# Generated by FakeRAM 2.0
VERSION 5.7 ;
BUSBITCHARS "[]" ;
PROPERTYDEFINITIONS
  MACRO width INTEGER ;
  MACRO depth INTEGER ;
  MACRO banks INTEGER ;
END PROPERTYDEFINITIONS
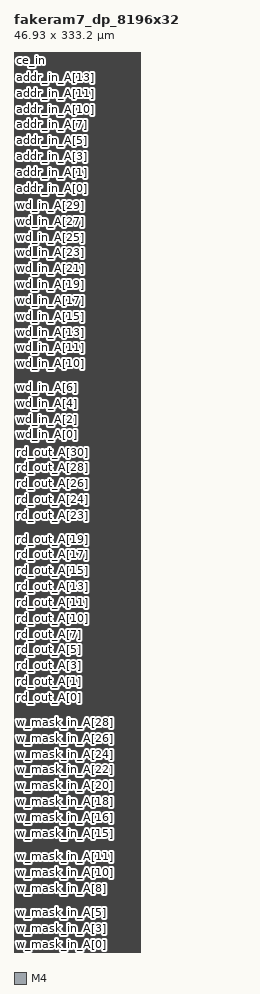
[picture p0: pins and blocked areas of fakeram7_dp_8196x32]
MACRO fakeram7_dp_8196x32
  PROPERTY width 32 ;
  PROPERTY depth 8196 ;
  PROPERTY banks 8 ;
  FOREIGN fakeram7_dp_8196x32 0 0 ;
  SYMMETRY X Y ;
  SIZE 46.930 BY 333.200 ;
  CLASS BLOCK ;
  PIN w_mask_in_A[0]
    DIRECTION INPUT ;
    USE SIGNAL ;
    SHAPE ABUTMENT ;
    PORT
      LAYER M4 ;
      RECT 0.000 0.048 0.024 0.072 ;
    END
  END w_mask_in_A[0]
  PIN w_mask_in_B[0]
    DIRECTION INPUT ;
    USE SIGNAL ;
    SHAPE ABUTMENT ;
    PORT
      LAYER M4 ;
      RECT 46.906 0.048 46.930 0.072 ;
    END
  END w_mask_in_B[0]
  PIN w_mask_in_A[1]
    DIRECTION INPUT ;
    USE SIGNAL ;
    SHAPE ABUTMENT ;
    PORT
      LAYER M4 ;
      RECT 0.000 2.976 0.024 3.000 ;
    END
  END w_mask_in_A[1]
  PIN w_mask_in_B[1]
    DIRECTION INPUT ;
    USE SIGNAL ;
    SHAPE ABUTMENT ;
    PORT
      LAYER M4 ;
      RECT 46.906 2.976 46.930 3.000 ;
    END
  END w_mask_in_B[1]
  PIN w_mask_in_A[2]
    DIRECTION INPUT ;
    USE SIGNAL ;
    SHAPE ABUTMENT ;
    PORT
      LAYER M4 ;
      RECT 0.000 5.904 0.024 5.928 ;
    END
  END w_mask_in_A[2]
  PIN w_mask_in_B[2]
    DIRECTION INPUT ;
    USE SIGNAL ;
    SHAPE ABUTMENT ;
    PORT
      LAYER M4 ;
      RECT 46.906 5.904 46.930 5.928 ;
    END
  END w_mask_in_B[2]
  PIN w_mask_in_A[3]
    DIRECTION INPUT ;
    USE SIGNAL ;
    SHAPE ABUTMENT ;
    PORT
      LAYER M4 ;
      RECT 0.000 8.832 0.024 8.856 ;
    END
  END w_mask_in_A[3]
  PIN w_mask_in_B[3]
    DIRECTION INPUT ;
    USE SIGNAL ;
    SHAPE ABUTMENT ;
    PORT
      LAYER M4 ;
      RECT 46.906 8.832 46.930 8.856 ;
    END
  END w_mask_in_B[3]
  PIN w_mask_in_A[4]
    DIRECTION INPUT ;
    USE SIGNAL ;
    SHAPE ABUTMENT ;
    PORT
      LAYER M4 ;
      RECT 0.000 11.760 0.024 11.784 ;
    END
  END w_mask_in_A[4]
  PIN w_mask_in_B[4]
    DIRECTION INPUT ;
    USE SIGNAL ;
    SHAPE ABUTMENT ;
    PORT
      LAYER M4 ;
      RECT 46.906 11.760 46.930 11.784 ;
    END
  END w_mask_in_B[4]
  PIN w_mask_in_A[5]
    DIRECTION INPUT ;
    USE SIGNAL ;
    SHAPE ABUTMENT ;
    PORT
      LAYER M4 ;
      RECT 0.000 14.688 0.024 14.712 ;
    END
  END w_mask_in_A[5]
  PIN w_mask_in_B[5]
    DIRECTION INPUT ;
    USE SIGNAL ;
    SHAPE ABUTMENT ;
    PORT
      LAYER M4 ;
      RECT 46.906 14.688 46.930 14.712 ;
    END
  END w_mask_in_B[5]
  PIN w_mask_in_A[6]
    DIRECTION INPUT ;
    USE SIGNAL ;
    SHAPE ABUTMENT ;
    PORT
      LAYER M4 ;
      RECT 0.000 17.616 0.024 17.640 ;
    END
  END w_mask_in_A[6]
  PIN w_mask_in_B[6]
    DIRECTION INPUT ;
    USE SIGNAL ;
    SHAPE ABUTMENT ;
    PORT
      LAYER M4 ;
      RECT 46.906 17.616 46.930 17.640 ;
    END
  END w_mask_in_B[6]
  PIN w_mask_in_A[7]
    DIRECTION INPUT ;
    USE SIGNAL ;
    SHAPE ABUTMENT ;
    PORT
      LAYER M4 ;
      RECT 0.000 20.544 0.024 20.568 ;
    END
  END w_mask_in_A[7]
  PIN w_mask_in_B[7]
    DIRECTION INPUT ;
    USE SIGNAL ;
    SHAPE ABUTMENT ;
    PORT
      LAYER M4 ;
      RECT 46.906 20.544 46.930 20.568 ;
    END
  END w_mask_in_B[7]
  PIN w_mask_in_A[8]
    DIRECTION INPUT ;
    USE SIGNAL ;
    SHAPE ABUTMENT ;
    PORT
      LAYER M4 ;
      RECT 0.000 23.472 0.024 23.496 ;
    END
  END w_mask_in_A[8]
  PIN w_mask_in_B[8]
    DIRECTION INPUT ;
    USE SIGNAL ;
    SHAPE ABUTMENT ;
    PORT
      LAYER M4 ;
      RECT 46.906 23.472 46.930 23.496 ;
    END
  END w_mask_in_B[8]
  PIN w_mask_in_A[9]
    DIRECTION INPUT ;
    USE SIGNAL ;
    SHAPE ABUTMENT ;
    PORT
      LAYER M4 ;
      RECT 0.000 26.400 0.024 26.424 ;
    END
  END w_mask_in_A[9]
  PIN w_mask_in_B[9]
    DIRECTION INPUT ;
    USE SIGNAL ;
    SHAPE ABUTMENT ;
    PORT
      LAYER M4 ;
      RECT 46.906 26.400 46.930 26.424 ;
    END
  END w_mask_in_B[9]
  PIN w_mask_in_A[10]
    DIRECTION INPUT ;
    USE SIGNAL ;
    SHAPE ABUTMENT ;
    PORT
      LAYER M4 ;
      RECT 0.000 29.328 0.024 29.352 ;
    END
  END w_mask_in_A[10]
  PIN w_mask_in_B[10]
    DIRECTION INPUT ;
    USE SIGNAL ;
    SHAPE ABUTMENT ;
    PORT
      LAYER M4 ;
      RECT 46.906 29.328 46.930 29.352 ;
    END
  END w_mask_in_B[10]
  PIN w_mask_in_A[11]
    DIRECTION INPUT ;
    USE SIGNAL ;
    SHAPE ABUTMENT ;
    PORT
      LAYER M4 ;
      RECT 0.000 32.256 0.024 32.280 ;
    END
  END w_mask_in_A[11]
  PIN w_mask_in_B[11]
    DIRECTION INPUT ;
    USE SIGNAL ;
    SHAPE ABUTMENT ;
    PORT
      LAYER M4 ;
      RECT 46.906 32.256 46.930 32.280 ;
    END
  END w_mask_in_B[11]
  PIN w_mask_in_A[12]
    DIRECTION INPUT ;
    USE SIGNAL ;
    SHAPE ABUTMENT ;
    PORT
      LAYER M4 ;
      RECT 0.000 35.184 0.024 35.208 ;
    END
  END w_mask_in_A[12]
  PIN w_mask_in_B[12]
    DIRECTION INPUT ;
    USE SIGNAL ;
    SHAPE ABUTMENT ;
    PORT
      LAYER M4 ;
      RECT 46.906 35.184 46.930 35.208 ;
    END
  END w_mask_in_B[12]
  PIN w_mask_in_A[13]
    DIRECTION INPUT ;
    USE SIGNAL ;
    SHAPE ABUTMENT ;
    PORT
      LAYER M4 ;
      RECT 0.000 38.112 0.024 38.136 ;
    END
  END w_mask_in_A[13]
  PIN w_mask_in_B[13]
    DIRECTION INPUT ;
    USE SIGNAL ;
    SHAPE ABUTMENT ;
    PORT
      LAYER M4 ;
      RECT 46.906 38.112 46.930 38.136 ;
    END
  END w_mask_in_B[13]
  PIN w_mask_in_A[14]
    DIRECTION INPUT ;
    USE SIGNAL ;
    SHAPE ABUTMENT ;
    PORT
      LAYER M4 ;
      RECT 0.000 41.040 0.024 41.064 ;
    END
  END w_mask_in_A[14]
  PIN w_mask_in_B[14]
    DIRECTION INPUT ;
    USE SIGNAL ;
    SHAPE ABUTMENT ;
    PORT
      LAYER M4 ;
      RECT 46.906 41.040 46.930 41.064 ;
    END
  END w_mask_in_B[14]
  PIN w_mask_in_A[15]
    DIRECTION INPUT ;
    USE SIGNAL ;
    SHAPE ABUTMENT ;
    PORT
      LAYER M4 ;
      RECT 0.000 43.968 0.024 43.992 ;
    END
  END w_mask_in_A[15]
  PIN w_mask_in_B[15]
    DIRECTION INPUT ;
    USE SIGNAL ;
    SHAPE ABUTMENT ;
    PORT
      LAYER M4 ;
      RECT 46.906 43.968 46.930 43.992 ;
    END
  END w_mask_in_B[15]
  PIN w_mask_in_A[16]
    DIRECTION INPUT ;
    USE SIGNAL ;
    SHAPE ABUTMENT ;
    PORT
      LAYER M4 ;
      RECT 0.000 46.896 0.024 46.920 ;
    END
  END w_mask_in_A[16]
  PIN w_mask_in_B[16]
    DIRECTION INPUT ;
    USE SIGNAL ;
    SHAPE ABUTMENT ;
    PORT
      LAYER M4 ;
      RECT 46.906 46.896 46.930 46.920 ;
    END
  END w_mask_in_B[16]
  PIN w_mask_in_A[17]
    DIRECTION INPUT ;
    USE SIGNAL ;
    SHAPE ABUTMENT ;
    PORT
      LAYER M4 ;
      RECT 0.000 49.824 0.024 49.848 ;
    END
  END w_mask_in_A[17]
  PIN w_mask_in_B[17]
    DIRECTION INPUT ;
    USE SIGNAL ;
    SHAPE ABUTMENT ;
    PORT
      LAYER M4 ;
      RECT 46.906 49.824 46.930 49.848 ;
    END
  END w_mask_in_B[17]
  PIN w_mask_in_A[18]
    DIRECTION INPUT ;
    USE SIGNAL ;
    SHAPE ABUTMENT ;
    PORT
      LAYER M4 ;
      RECT 0.000 52.752 0.024 52.776 ;
    END
  END w_mask_in_A[18]
  PIN w_mask_in_B[18]
    DIRECTION INPUT ;
    USE SIGNAL ;
    SHAPE ABUTMENT ;
    PORT
      LAYER M4 ;
      RECT 46.906 52.752 46.930 52.776 ;
    END
  END w_mask_in_B[18]
  PIN w_mask_in_A[19]
    DIRECTION INPUT ;
    USE SIGNAL ;
    SHAPE ABUTMENT ;
    PORT
      LAYER M4 ;
      RECT 0.000 55.680 0.024 55.704 ;
    END
  END w_mask_in_A[19]
  PIN w_mask_in_B[19]
    DIRECTION INPUT ;
    USE SIGNAL ;
    SHAPE ABUTMENT ;
    PORT
      LAYER M4 ;
      RECT 46.906 55.680 46.930 55.704 ;
    END
  END w_mask_in_B[19]
  PIN w_mask_in_A[20]
    DIRECTION INPUT ;
    USE SIGNAL ;
    SHAPE ABUTMENT ;
    PORT
      LAYER M4 ;
      RECT 0.000 58.608 0.024 58.632 ;
    END
  END w_mask_in_A[20]
  PIN w_mask_in_B[20]
    DIRECTION INPUT ;
    USE SIGNAL ;
    SHAPE ABUTMENT ;
    PORT
      LAYER M4 ;
      RECT 46.906 58.608 46.930 58.632 ;
    END
  END w_mask_in_B[20]
  PIN w_mask_in_A[21]
    DIRECTION INPUT ;
    USE SIGNAL ;
    SHAPE ABUTMENT ;
    PORT
      LAYER M4 ;
      RECT 0.000 61.536 0.024 61.560 ;
    END
  END w_mask_in_A[21]
  PIN w_mask_in_B[21]
    DIRECTION INPUT ;
    USE SIGNAL ;
    SHAPE ABUTMENT ;
    PORT
      LAYER M4 ;
      RECT 46.906 61.536 46.930 61.560 ;
    END
  END w_mask_in_B[21]
  PIN w_mask_in_A[22]
    DIRECTION INPUT ;
    USE SIGNAL ;
    SHAPE ABUTMENT ;
    PORT
      LAYER M4 ;
      RECT 0.000 64.464 0.024 64.488 ;
    END
  END w_mask_in_A[22]
  PIN w_mask_in_B[22]
    DIRECTION INPUT ;
    USE SIGNAL ;
    SHAPE ABUTMENT ;
    PORT
      LAYER M4 ;
      RECT 46.906 64.464 46.930 64.488 ;
    END
  END w_mask_in_B[22]
  PIN w_mask_in_A[23]
    DIRECTION INPUT ;
    USE SIGNAL ;
    SHAPE ABUTMENT ;
    PORT
      LAYER M4 ;
      RECT 0.000 67.392 0.024 67.416 ;
    END
  END w_mask_in_A[23]
  PIN w_mask_in_B[23]
    DIRECTION INPUT ;
    USE SIGNAL ;
    SHAPE ABUTMENT ;
    PORT
      LAYER M4 ;
      RECT 46.906 67.392 46.930 67.416 ;
    END
  END w_mask_in_B[23]
  PIN w_mask_in_A[24]
    DIRECTION INPUT ;
    USE SIGNAL ;
    SHAPE ABUTMENT ;
    PORT
      LAYER M4 ;
      RECT 0.000 70.320 0.024 70.344 ;
    END
  END w_mask_in_A[24]
  PIN w_mask_in_B[24]
    DIRECTION INPUT ;
    USE SIGNAL ;
    SHAPE ABUTMENT ;
    PORT
      LAYER M4 ;
      RECT 46.906 70.320 46.930 70.344 ;
    END
  END w_mask_in_B[24]
  PIN w_mask_in_A[25]
    DIRECTION INPUT ;
    USE SIGNAL ;
    SHAPE ABUTMENT ;
    PORT
      LAYER M4 ;
      RECT 0.000 73.248 0.024 73.272 ;
    END
  END w_mask_in_A[25]
  PIN w_mask_in_B[25]
    DIRECTION INPUT ;
    USE SIGNAL ;
    SHAPE ABUTMENT ;
    PORT
      LAYER M4 ;
      RECT 46.906 73.248 46.930 73.272 ;
    END
  END w_mask_in_B[25]
  PIN w_mask_in_A[26]
    DIRECTION INPUT ;
    USE SIGNAL ;
    SHAPE ABUTMENT ;
    PORT
      LAYER M4 ;
      RECT 0.000 76.176 0.024 76.200 ;
    END
  END w_mask_in_A[26]
  PIN w_mask_in_B[26]
    DIRECTION INPUT ;
    USE SIGNAL ;
    SHAPE ABUTMENT ;
    PORT
      LAYER M4 ;
      RECT 46.906 76.176 46.930 76.200 ;
    END
  END w_mask_in_B[26]
  PIN w_mask_in_A[27]
    DIRECTION INPUT ;
    USE SIGNAL ;
    SHAPE ABUTMENT ;
    PORT
      LAYER M4 ;
      RECT 0.000 79.104 0.024 79.128 ;
    END
  END w_mask_in_A[27]
  PIN w_mask_in_B[27]
    DIRECTION INPUT ;
    USE SIGNAL ;
    SHAPE ABUTMENT ;
    PORT
      LAYER M4 ;
      RECT 46.906 79.104 46.930 79.128 ;
    END
  END w_mask_in_B[27]
  PIN w_mask_in_A[28]
    DIRECTION INPUT ;
    USE SIGNAL ;
    SHAPE ABUTMENT ;
    PORT
      LAYER M4 ;
      RECT 0.000 82.032 0.024 82.056 ;
    END
  END w_mask_in_A[28]
  PIN w_mask_in_B[28]
    DIRECTION INPUT ;
    USE SIGNAL ;
    SHAPE ABUTMENT ;
    PORT
      LAYER M4 ;
      RECT 46.906 82.032 46.930 82.056 ;
    END
  END w_mask_in_B[28]
  PIN w_mask_in_A[29]
    DIRECTION INPUT ;
    USE SIGNAL ;
    SHAPE ABUTMENT ;
    PORT
      LAYER M4 ;
      RECT 0.000 84.960 0.024 84.984 ;
    END
  END w_mask_in_A[29]
  PIN w_mask_in_B[29]
    DIRECTION INPUT ;
    USE SIGNAL ;
    SHAPE ABUTMENT ;
    PORT
      LAYER M4 ;
      RECT 46.906 84.960 46.930 84.984 ;
    END
  END w_mask_in_B[29]
  PIN w_mask_in_A[30]
    DIRECTION INPUT ;
    USE SIGNAL ;
    SHAPE ABUTMENT ;
    PORT
      LAYER M4 ;
      RECT 0.000 87.888 0.024 87.912 ;
    END
  END w_mask_in_A[30]
  PIN w_mask_in_B[30]
    DIRECTION INPUT ;
    USE SIGNAL ;
    SHAPE ABUTMENT ;
    PORT
      LAYER M4 ;
      RECT 46.906 87.888 46.930 87.912 ;
    END
  END w_mask_in_B[30]
  PIN w_mask_in_A[31]
    DIRECTION INPUT ;
    USE SIGNAL ;
    SHAPE ABUTMENT ;
    PORT
      LAYER M4 ;
      RECT 0.000 90.816 0.024 90.840 ;
    END
  END w_mask_in_A[31]
  PIN w_mask_in_B[31]
    DIRECTION INPUT ;
    USE SIGNAL ;
    SHAPE ABUTMENT ;
    PORT
      LAYER M4 ;
      RECT 46.906 90.816 46.930 90.840 ;
    END
  END w_mask_in_B[31]
  PIN rd_out_A[0]
    DIRECTION OUTPUT ;
    USE SIGNAL ;
    SHAPE ABUTMENT ;
    PORT
      LAYER M4 ;
      RECT 0.000 94.272 0.024 94.296 ;
    END
  END rd_out_A[0]
  PIN rd_out_B[0]
    DIRECTION OUTPUT ;
    USE SIGNAL ;
    SHAPE ABUTMENT ;
    PORT
      LAYER M4 ;
      RECT 46.906 94.272 46.930 94.296 ;
    END
  END rd_out_B[0]
  PIN rd_out_A[1]
    DIRECTION OUTPUT ;
    USE SIGNAL ;
    SHAPE ABUTMENT ;
    PORT
      LAYER M4 ;
      RECT 0.000 97.200 0.024 97.224 ;
    END
  END rd_out_A[1]
  PIN rd_out_B[1]
    DIRECTION OUTPUT ;
    USE SIGNAL ;
    SHAPE ABUTMENT ;
    PORT
      LAYER M4 ;
      RECT 46.906 97.200 46.930 97.224 ;
    END
  END rd_out_B[1]
  PIN rd_out_A[2]
    DIRECTION OUTPUT ;
    USE SIGNAL ;
    SHAPE ABUTMENT ;
    PORT
      LAYER M4 ;
      RECT 0.000 100.128 0.024 100.152 ;
    END
  END rd_out_A[2]
  PIN rd_out_B[2]
    DIRECTION OUTPUT ;
    USE SIGNAL ;
    SHAPE ABUTMENT ;
    PORT
      LAYER M4 ;
      RECT 46.906 100.128 46.930 100.152 ;
    END
  END rd_out_B[2]
  PIN rd_out_A[3]
    DIRECTION OUTPUT ;
    USE SIGNAL ;
    SHAPE ABUTMENT ;
    PORT
      LAYER M4 ;
      RECT 0.000 103.056 0.024 103.080 ;
    END
  END rd_out_A[3]
  PIN rd_out_B[3]
    DIRECTION OUTPUT ;
    USE SIGNAL ;
    SHAPE ABUTMENT ;
    PORT
      LAYER M4 ;
      RECT 46.906 103.056 46.930 103.080 ;
    END
  END rd_out_B[3]
  PIN rd_out_A[4]
    DIRECTION OUTPUT ;
    USE SIGNAL ;
    SHAPE ABUTMENT ;
    PORT
      LAYER M4 ;
      RECT 0.000 105.984 0.024 106.008 ;
    END
  END rd_out_A[4]
  PIN rd_out_B[4]
    DIRECTION OUTPUT ;
    USE SIGNAL ;
    SHAPE ABUTMENT ;
    PORT
      LAYER M4 ;
      RECT 46.906 105.984 46.930 106.008 ;
    END
  END rd_out_B[4]
  PIN rd_out_A[5]
    DIRECTION OUTPUT ;
    USE SIGNAL ;
    SHAPE ABUTMENT ;
    PORT
      LAYER M4 ;
      RECT 0.000 108.912 0.024 108.936 ;
    END
  END rd_out_A[5]
  PIN rd_out_B[5]
    DIRECTION OUTPUT ;
    USE SIGNAL ;
    SHAPE ABUTMENT ;
    PORT
      LAYER M4 ;
      RECT 46.906 108.912 46.930 108.936 ;
    END
  END rd_out_B[5]
  PIN rd_out_A[6]
    DIRECTION OUTPUT ;
    USE SIGNAL ;
    SHAPE ABUTMENT ;
    PORT
      LAYER M4 ;
      RECT 0.000 111.840 0.024 111.864 ;
    END
  END rd_out_A[6]
  PIN rd_out_B[6]
    DIRECTION OUTPUT ;
    USE SIGNAL ;
    SHAPE ABUTMENT ;
    PORT
      LAYER M4 ;
      RECT 46.906 111.840 46.930 111.864 ;
    END
  END rd_out_B[6]
  PIN rd_out_A[7]
    DIRECTION OUTPUT ;
    USE SIGNAL ;
    SHAPE ABUTMENT ;
    PORT
      LAYER M4 ;
      RECT 0.000 114.768 0.024 114.792 ;
    END
  END rd_out_A[7]
  PIN rd_out_B[7]
    DIRECTION OUTPUT ;
    USE SIGNAL ;
    SHAPE ABUTMENT ;
    PORT
      LAYER M4 ;
      RECT 46.906 114.768 46.930 114.792 ;
    END
  END rd_out_B[7]
  PIN rd_out_A[8]
    DIRECTION OUTPUT ;
    USE SIGNAL ;
    SHAPE ABUTMENT ;
    PORT
      LAYER M4 ;
      RECT 0.000 117.696 0.024 117.720 ;
    END
  END rd_out_A[8]
  PIN rd_out_B[8]
    DIRECTION OUTPUT ;
    USE SIGNAL ;
    SHAPE ABUTMENT ;
    PORT
      LAYER M4 ;
      RECT 46.906 117.696 46.930 117.720 ;
    END
  END rd_out_B[8]
  PIN rd_out_A[9]
    DIRECTION OUTPUT ;
    USE SIGNAL ;
    SHAPE ABUTMENT ;
    PORT
      LAYER M4 ;
      RECT 0.000 120.624 0.024 120.648 ;
    END
  END rd_out_A[9]
  PIN rd_out_B[9]
    DIRECTION OUTPUT ;
    USE SIGNAL ;
    SHAPE ABUTMENT ;
    PORT
      LAYER M4 ;
      RECT 46.906 120.624 46.930 120.648 ;
    END
  END rd_out_B[9]
  PIN rd_out_A[10]
    DIRECTION OUTPUT ;
    USE SIGNAL ;
    SHAPE ABUTMENT ;
    PORT
      LAYER M4 ;
      RECT 0.000 123.552 0.024 123.576 ;
    END
  END rd_out_A[10]
  PIN rd_out_B[10]
    DIRECTION OUTPUT ;
    USE SIGNAL ;
    SHAPE ABUTMENT ;
    PORT
      LAYER M4 ;
      RECT 46.906 123.552 46.930 123.576 ;
    END
  END rd_out_B[10]
  PIN rd_out_A[11]
    DIRECTION OUTPUT ;
    USE SIGNAL ;
    SHAPE ABUTMENT ;
    PORT
      LAYER M4 ;
      RECT 0.000 126.480 0.024 126.504 ;
    END
  END rd_out_A[11]
  PIN rd_out_B[11]
    DIRECTION OUTPUT ;
    USE SIGNAL ;
    SHAPE ABUTMENT ;
    PORT
      LAYER M4 ;
      RECT 46.906 126.480 46.930 126.504 ;
    END
  END rd_out_B[11]
  PIN rd_out_A[12]
    DIRECTION OUTPUT ;
    USE SIGNAL ;
    SHAPE ABUTMENT ;
    PORT
      LAYER M4 ;
      RECT 0.000 129.408 0.024 129.432 ;
    END
  END rd_out_A[12]
  PIN rd_out_B[12]
    DIRECTION OUTPUT ;
    USE SIGNAL ;
    SHAPE ABUTMENT ;
    PORT
      LAYER M4 ;
      RECT 46.906 129.408 46.930 129.432 ;
    END
  END rd_out_B[12]
  PIN rd_out_A[13]
    DIRECTION OUTPUT ;
    USE SIGNAL ;
    SHAPE ABUTMENT ;
    PORT
      LAYER M4 ;
      RECT 0.000 132.336 0.024 132.360 ;
    END
  END rd_out_A[13]
  PIN rd_out_B[13]
    DIRECTION OUTPUT ;
    USE SIGNAL ;
    SHAPE ABUTMENT ;
    PORT
      LAYER M4 ;
      RECT 46.906 132.336 46.930 132.360 ;
    END
  END rd_out_B[13]
  PIN rd_out_A[14]
    DIRECTION OUTPUT ;
    USE SIGNAL ;
    SHAPE ABUTMENT ;
    PORT
      LAYER M4 ;
      RECT 0.000 135.264 0.024 135.288 ;
    END
  END rd_out_A[14]
  PIN rd_out_B[14]
    DIRECTION OUTPUT ;
    USE SIGNAL ;
    SHAPE ABUTMENT ;
    PORT
      LAYER M4 ;
      RECT 46.906 135.264 46.930 135.288 ;
    END
  END rd_out_B[14]
  PIN rd_out_A[15]
    DIRECTION OUTPUT ;
    USE SIGNAL ;
    SHAPE ABUTMENT ;
    PORT
      LAYER M4 ;
      RECT 0.000 138.192 0.024 138.216 ;
    END
  END rd_out_A[15]
  PIN rd_out_B[15]
    DIRECTION OUTPUT ;
    USE SIGNAL ;
    SHAPE ABUTMENT ;
    PORT
      LAYER M4 ;
      RECT 46.906 138.192 46.930 138.216 ;
    END
  END rd_out_B[15]
  PIN rd_out_A[16]
    DIRECTION OUTPUT ;
    USE SIGNAL ;
    SHAPE ABUTMENT ;
    PORT
      LAYER M4 ;
      RECT 0.000 141.120 0.024 141.144 ;
    END
  END rd_out_A[16]
  PIN rd_out_B[16]
    DIRECTION OUTPUT ;
    USE SIGNAL ;
    SHAPE ABUTMENT ;
    PORT
      LAYER M4 ;
      RECT 46.906 141.120 46.930 141.144 ;
    END
  END rd_out_B[16]
  PIN rd_out_A[17]
    DIRECTION OUTPUT ;
    USE SIGNAL ;
    SHAPE ABUTMENT ;
    PORT
      LAYER M4 ;
      RECT 0.000 144.048 0.024 144.072 ;
    END
  END rd_out_A[17]
  PIN rd_out_B[17]
    DIRECTION OUTPUT ;
    USE SIGNAL ;
    SHAPE ABUTMENT ;
    PORT
      LAYER M4 ;
      RECT 46.906 144.048 46.930 144.072 ;
    END
  END rd_out_B[17]
  PIN rd_out_A[18]
    DIRECTION OUTPUT ;
    USE SIGNAL ;
    SHAPE ABUTMENT ;
    PORT
      LAYER M4 ;
      RECT 0.000 146.976 0.024 147.000 ;
    END
  END rd_out_A[18]
  PIN rd_out_B[18]
    DIRECTION OUTPUT ;
    USE SIGNAL ;
    SHAPE ABUTMENT ;
    PORT
      LAYER M4 ;
      RECT 46.906 146.976 46.930 147.000 ;
    END
  END rd_out_B[18]
  PIN rd_out_A[19]
    DIRECTION OUTPUT ;
    USE SIGNAL ;
    SHAPE ABUTMENT ;
    PORT
      LAYER M4 ;
      RECT 0.000 149.904 0.024 149.928 ;
    END
  END rd_out_A[19]
  PIN rd_out_B[19]
    DIRECTION OUTPUT ;
    USE SIGNAL ;
    SHAPE ABUTMENT ;
    PORT
      LAYER M4 ;
      RECT 46.906 149.904 46.930 149.928 ;
    END
  END rd_out_B[19]
  PIN rd_out_A[20]
    DIRECTION OUTPUT ;
    USE SIGNAL ;
    SHAPE ABUTMENT ;
    PORT
      LAYER M4 ;
      RECT 0.000 152.832 0.024 152.856 ;
    END
  END rd_out_A[20]
  PIN rd_out_B[20]
    DIRECTION OUTPUT ;
    USE SIGNAL ;
    SHAPE ABUTMENT ;
    PORT
      LAYER M4 ;
      RECT 46.906 152.832 46.930 152.856 ;
    END
  END rd_out_B[20]
  PIN rd_out_A[21]
    DIRECTION OUTPUT ;
    USE SIGNAL ;
    SHAPE ABUTMENT ;
    PORT
      LAYER M4 ;
      RECT 0.000 155.760 0.024 155.784 ;
    END
  END rd_out_A[21]
  PIN rd_out_B[21]
    DIRECTION OUTPUT ;
    USE SIGNAL ;
    SHAPE ABUTMENT ;
    PORT
      LAYER M4 ;
      RECT 46.906 155.760 46.930 155.784 ;
    END
  END rd_out_B[21]
  PIN rd_out_A[22]
    DIRECTION OUTPUT ;
    USE SIGNAL ;
    SHAPE ABUTMENT ;
    PORT
      LAYER M4 ;
      RECT 0.000 158.688 0.024 158.712 ;
    END
  END rd_out_A[22]
  PIN rd_out_B[22]
    DIRECTION OUTPUT ;
    USE SIGNAL ;
    SHAPE ABUTMENT ;
    PORT
      LAYER M4 ;
      RECT 46.906 158.688 46.930 158.712 ;
    END
  END rd_out_B[22]
  PIN rd_out_A[23]
    DIRECTION OUTPUT ;
    USE SIGNAL ;
    SHAPE ABUTMENT ;
    PORT
      LAYER M4 ;
      RECT 0.000 161.616 0.024 161.640 ;
    END
  END rd_out_A[23]
  PIN rd_out_B[23]
    DIRECTION OUTPUT ;
    USE SIGNAL ;
    SHAPE ABUTMENT ;
    PORT
      LAYER M4 ;
      RECT 46.906 161.616 46.930 161.640 ;
    END
  END rd_out_B[23]
  PIN rd_out_A[24]
    DIRECTION OUTPUT ;
    USE SIGNAL ;
    SHAPE ABUTMENT ;
    PORT
      LAYER M4 ;
      RECT 0.000 164.544 0.024 164.568 ;
    END
  END rd_out_A[24]
  PIN rd_out_B[24]
    DIRECTION OUTPUT ;
    USE SIGNAL ;
    SHAPE ABUTMENT ;
    PORT
      LAYER M4 ;
      RECT 46.906 164.544 46.930 164.568 ;
    END
  END rd_out_B[24]
  PIN rd_out_A[25]
    DIRECTION OUTPUT ;
    USE SIGNAL ;
    SHAPE ABUTMENT ;
    PORT
      LAYER M4 ;
      RECT 0.000 167.472 0.024 167.496 ;
    END
  END rd_out_A[25]
  PIN rd_out_B[25]
    DIRECTION OUTPUT ;
    USE SIGNAL ;
    SHAPE ABUTMENT ;
    PORT
      LAYER M4 ;
      RECT 46.906 167.472 46.930 167.496 ;
    END
  END rd_out_B[25]
  PIN rd_out_A[26]
    DIRECTION OUTPUT ;
    USE SIGNAL ;
    SHAPE ABUTMENT ;
    PORT
      LAYER M4 ;
      RECT 0.000 170.400 0.024 170.424 ;
    END
  END rd_out_A[26]
  PIN rd_out_B[26]
    DIRECTION OUTPUT ;
    USE SIGNAL ;
    SHAPE ABUTMENT ;
    PORT
      LAYER M4 ;
      RECT 46.906 170.400 46.930 170.424 ;
    END
  END rd_out_B[26]
  PIN rd_out_A[27]
    DIRECTION OUTPUT ;
    USE SIGNAL ;
    SHAPE ABUTMENT ;
    PORT
      LAYER M4 ;
      RECT 0.000 173.328 0.024 173.352 ;
    END
  END rd_out_A[27]
  PIN rd_out_B[27]
    DIRECTION OUTPUT ;
    USE SIGNAL ;
    SHAPE ABUTMENT ;
    PORT
      LAYER M4 ;
      RECT 46.906 173.328 46.930 173.352 ;
    END
  END rd_out_B[27]
  PIN rd_out_A[28]
    DIRECTION OUTPUT ;
    USE SIGNAL ;
    SHAPE ABUTMENT ;
    PORT
      LAYER M4 ;
      RECT 0.000 176.256 0.024 176.280 ;
    END
  END rd_out_A[28]
  PIN rd_out_B[28]
    DIRECTION OUTPUT ;
    USE SIGNAL ;
    SHAPE ABUTMENT ;
    PORT
      LAYER M4 ;
      RECT 46.906 176.256 46.930 176.280 ;
    END
  END rd_out_B[28]
  PIN rd_out_A[29]
    DIRECTION OUTPUT ;
    USE SIGNAL ;
    SHAPE ABUTMENT ;
    PORT
      LAYER M4 ;
      RECT 0.000 179.184 0.024 179.208 ;
    END
  END rd_out_A[29]
  PIN rd_out_B[29]
    DIRECTION OUTPUT ;
    USE SIGNAL ;
    SHAPE ABUTMENT ;
    PORT
      LAYER M4 ;
      RECT 46.906 179.184 46.930 179.208 ;
    END
  END rd_out_B[29]
  PIN rd_out_A[30]
    DIRECTION OUTPUT ;
    USE SIGNAL ;
    SHAPE ABUTMENT ;
    PORT
      LAYER M4 ;
      RECT 0.000 182.112 0.024 182.136 ;
    END
  END rd_out_A[30]
  PIN rd_out_B[30]
    DIRECTION OUTPUT ;
    USE SIGNAL ;
    SHAPE ABUTMENT ;
    PORT
      LAYER M4 ;
      RECT 46.906 182.112 46.930 182.136 ;
    END
  END rd_out_B[30]
  PIN rd_out_A[31]
    DIRECTION OUTPUT ;
    USE SIGNAL ;
    SHAPE ABUTMENT ;
    PORT
      LAYER M4 ;
      RECT 0.000 185.040 0.024 185.064 ;
    END
  END rd_out_A[31]
  PIN rd_out_B[31]
    DIRECTION OUTPUT ;
    USE SIGNAL ;
    SHAPE ABUTMENT ;
    PORT
      LAYER M4 ;
      RECT 46.906 185.040 46.930 185.064 ;
    END
  END rd_out_B[31]
  PIN wd_in_A[0]
    DIRECTION INPUT ;
    USE SIGNAL ;
    SHAPE ABUTMENT ;
    PORT
      LAYER M4 ;
      RECT 0.000 188.496 0.024 188.520 ;
    END
  END wd_in_A[0]
  PIN wd_in_B[0]
    DIRECTION INPUT ;
    USE SIGNAL ;
    SHAPE ABUTMENT ;
    PORT
      LAYER M4 ;
      RECT 46.906 188.496 46.930 188.520 ;
    END
  END wd_in_B[0]
  PIN wd_in_A[1]
    DIRECTION INPUT ;
    USE SIGNAL ;
    SHAPE ABUTMENT ;
    PORT
      LAYER M4 ;
      RECT 0.000 191.424 0.024 191.448 ;
    END
  END wd_in_A[1]
  PIN wd_in_B[1]
    DIRECTION INPUT ;
    USE SIGNAL ;
    SHAPE ABUTMENT ;
    PORT
      LAYER M4 ;
      RECT 46.906 191.424 46.930 191.448 ;
    END
  END wd_in_B[1]
  PIN wd_in_A[2]
    DIRECTION INPUT ;
    USE SIGNAL ;
    SHAPE ABUTMENT ;
    PORT
      LAYER M4 ;
      RECT 0.000 194.352 0.024 194.376 ;
    END
  END wd_in_A[2]
  PIN wd_in_B[2]
    DIRECTION INPUT ;
    USE SIGNAL ;
    SHAPE ABUTMENT ;
    PORT
      LAYER M4 ;
      RECT 46.906 194.352 46.930 194.376 ;
    END
  END wd_in_B[2]
  PIN wd_in_A[3]
    DIRECTION INPUT ;
    USE SIGNAL ;
    SHAPE ABUTMENT ;
    PORT
      LAYER M4 ;
      RECT 0.000 197.280 0.024 197.304 ;
    END
  END wd_in_A[3]
  PIN wd_in_B[3]
    DIRECTION INPUT ;
    USE SIGNAL ;
    SHAPE ABUTMENT ;
    PORT
      LAYER M4 ;
      RECT 46.906 197.280 46.930 197.304 ;
    END
  END wd_in_B[3]
  PIN wd_in_A[4]
    DIRECTION INPUT ;
    USE SIGNAL ;
    SHAPE ABUTMENT ;
    PORT
      LAYER M4 ;
      RECT 0.000 200.208 0.024 200.232 ;
    END
  END wd_in_A[4]
  PIN wd_in_B[4]
    DIRECTION INPUT ;
    USE SIGNAL ;
    SHAPE ABUTMENT ;
    PORT
      LAYER M4 ;
      RECT 46.906 200.208 46.930 200.232 ;
    END
  END wd_in_B[4]
  PIN wd_in_A[5]
    DIRECTION INPUT ;
    USE SIGNAL ;
    SHAPE ABUTMENT ;
    PORT
      LAYER M4 ;
      RECT 0.000 203.136 0.024 203.160 ;
    END
  END wd_in_A[5]
  PIN wd_in_B[5]
    DIRECTION INPUT ;
    USE SIGNAL ;
    SHAPE ABUTMENT ;
    PORT
      LAYER M4 ;
      RECT 46.906 203.136 46.930 203.160 ;
    END
  END wd_in_B[5]
  PIN wd_in_A[6]
    DIRECTION INPUT ;
    USE SIGNAL ;
    SHAPE ABUTMENT ;
    PORT
      LAYER M4 ;
      RECT 0.000 206.064 0.024 206.088 ;
    END
  END wd_in_A[6]
  PIN wd_in_B[6]
    DIRECTION INPUT ;
    USE SIGNAL ;
    SHAPE ABUTMENT ;
    PORT
      LAYER M4 ;
      RECT 46.906 206.064 46.930 206.088 ;
    END
  END wd_in_B[6]
  PIN wd_in_A[7]
    DIRECTION INPUT ;
    USE SIGNAL ;
    SHAPE ABUTMENT ;
    PORT
      LAYER M4 ;
      RECT 0.000 208.992 0.024 209.016 ;
    END
  END wd_in_A[7]
  PIN wd_in_B[7]
    DIRECTION INPUT ;
    USE SIGNAL ;
    SHAPE ABUTMENT ;
    PORT
      LAYER M4 ;
      RECT 46.906 208.992 46.930 209.016 ;
    END
  END wd_in_B[7]
  PIN wd_in_A[8]
    DIRECTION INPUT ;
    USE SIGNAL ;
    SHAPE ABUTMENT ;
    PORT
      LAYER M4 ;
      RECT 0.000 211.920 0.024 211.944 ;
    END
  END wd_in_A[8]
  PIN wd_in_B[8]
    DIRECTION INPUT ;
    USE SIGNAL ;
    SHAPE ABUTMENT ;
    PORT
      LAYER M4 ;
      RECT 46.906 211.920 46.930 211.944 ;
    END
  END wd_in_B[8]
  PIN wd_in_A[9]
    DIRECTION INPUT ;
    USE SIGNAL ;
    SHAPE ABUTMENT ;
    PORT
      LAYER M4 ;
      RECT 0.000 214.848 0.024 214.872 ;
    END
  END wd_in_A[9]
  PIN wd_in_B[9]
    DIRECTION INPUT ;
    USE SIGNAL ;
    SHAPE ABUTMENT ;
    PORT
      LAYER M4 ;
      RECT 46.906 214.848 46.930 214.872 ;
    END
  END wd_in_B[9]
  PIN wd_in_A[10]
    DIRECTION INPUT ;
    USE SIGNAL ;
    SHAPE ABUTMENT ;
    PORT
      LAYER M4 ;
      RECT 0.000 217.776 0.024 217.800 ;
    END
  END wd_in_A[10]
  PIN wd_in_B[10]
    DIRECTION INPUT ;
    USE SIGNAL ;
    SHAPE ABUTMENT ;
    PORT
      LAYER M4 ;
      RECT 46.906 217.776 46.930 217.800 ;
    END
  END wd_in_B[10]
  PIN wd_in_A[11]
    DIRECTION INPUT ;
    USE SIGNAL ;
    SHAPE ABUTMENT ;
    PORT
      LAYER M4 ;
      RECT 0.000 220.704 0.024 220.728 ;
    END
  END wd_in_A[11]
  PIN wd_in_B[11]
    DIRECTION INPUT ;
    USE SIGNAL ;
    SHAPE ABUTMENT ;
    PORT
      LAYER M4 ;
      RECT 46.906 220.704 46.930 220.728 ;
    END
  END wd_in_B[11]
  PIN wd_in_A[12]
    DIRECTION INPUT ;
    USE SIGNAL ;
    SHAPE ABUTMENT ;
    PORT
      LAYER M4 ;
      RECT 0.000 223.632 0.024 223.656 ;
    END
  END wd_in_A[12]
  PIN wd_in_B[12]
    DIRECTION INPUT ;
    USE SIGNAL ;
    SHAPE ABUTMENT ;
    PORT
      LAYER M4 ;
      RECT 46.906 223.632 46.930 223.656 ;
    END
  END wd_in_B[12]
  PIN wd_in_A[13]
    DIRECTION INPUT ;
    USE SIGNAL ;
    SHAPE ABUTMENT ;
    PORT
      LAYER M4 ;
      RECT 0.000 226.560 0.024 226.584 ;
    END
  END wd_in_A[13]
  PIN wd_in_B[13]
    DIRECTION INPUT ;
    USE SIGNAL ;
    SHAPE ABUTMENT ;
    PORT
      LAYER M4 ;
      RECT 46.906 226.560 46.930 226.584 ;
    END
  END wd_in_B[13]
  PIN wd_in_A[14]
    DIRECTION INPUT ;
    USE SIGNAL ;
    SHAPE ABUTMENT ;
    PORT
      LAYER M4 ;
      RECT 0.000 229.488 0.024 229.512 ;
    END
  END wd_in_A[14]
  PIN wd_in_B[14]
    DIRECTION INPUT ;
    USE SIGNAL ;
    SHAPE ABUTMENT ;
    PORT
      LAYER M4 ;
      RECT 46.906 229.488 46.930 229.512 ;
    END
  END wd_in_B[14]
  PIN wd_in_A[15]
    DIRECTION INPUT ;
    USE SIGNAL ;
    SHAPE ABUTMENT ;
    PORT
      LAYER M4 ;
      RECT 0.000 232.416 0.024 232.440 ;
    END
  END wd_in_A[15]
  PIN wd_in_B[15]
    DIRECTION INPUT ;
    USE SIGNAL ;
    SHAPE ABUTMENT ;
    PORT
      LAYER M4 ;
      RECT 46.906 232.416 46.930 232.440 ;
    END
  END wd_in_B[15]
  PIN wd_in_A[16]
    DIRECTION INPUT ;
    USE SIGNAL ;
    SHAPE ABUTMENT ;
    PORT
      LAYER M4 ;
      RECT 0.000 235.344 0.024 235.368 ;
    END
  END wd_in_A[16]
  PIN wd_in_B[16]
    DIRECTION INPUT ;
    USE SIGNAL ;
    SHAPE ABUTMENT ;
    PORT
      LAYER M4 ;
      RECT 46.906 235.344 46.930 235.368 ;
    END
  END wd_in_B[16]
  PIN wd_in_A[17]
    DIRECTION INPUT ;
    USE SIGNAL ;
    SHAPE ABUTMENT ;
    PORT
      LAYER M4 ;
      RECT 0.000 238.272 0.024 238.296 ;
    END
  END wd_in_A[17]
  PIN wd_in_B[17]
    DIRECTION INPUT ;
    USE SIGNAL ;
    SHAPE ABUTMENT ;
    PORT
      LAYER M4 ;
      RECT 46.906 238.272 46.930 238.296 ;
    END
  END wd_in_B[17]
  PIN wd_in_A[18]
    DIRECTION INPUT ;
    USE SIGNAL ;
    SHAPE ABUTMENT ;
    PORT
      LAYER M4 ;
      RECT 0.000 241.200 0.024 241.224 ;
    END
  END wd_in_A[18]
  PIN wd_in_B[18]
    DIRECTION INPUT ;
    USE SIGNAL ;
    SHAPE ABUTMENT ;
    PORT
      LAYER M4 ;
      RECT 46.906 241.200 46.930 241.224 ;
    END
  END wd_in_B[18]
  PIN wd_in_A[19]
    DIRECTION INPUT ;
    USE SIGNAL ;
    SHAPE ABUTMENT ;
    PORT
      LAYER M4 ;
      RECT 0.000 244.128 0.024 244.152 ;
    END
  END wd_in_A[19]
  PIN wd_in_B[19]
    DIRECTION INPUT ;
    USE SIGNAL ;
    SHAPE ABUTMENT ;
    PORT
      LAYER M4 ;
      RECT 46.906 244.128 46.930 244.152 ;
    END
  END wd_in_B[19]
  PIN wd_in_A[20]
    DIRECTION INPUT ;
    USE SIGNAL ;
    SHAPE ABUTMENT ;
    PORT
      LAYER M4 ;
      RECT 0.000 247.056 0.024 247.080 ;
    END
  END wd_in_A[20]
  PIN wd_in_B[20]
    DIRECTION INPUT ;
    USE SIGNAL ;
    SHAPE ABUTMENT ;
    PORT
      LAYER M4 ;
      RECT 46.906 247.056 46.930 247.080 ;
    END
  END wd_in_B[20]
  PIN wd_in_A[21]
    DIRECTION INPUT ;
    USE SIGNAL ;
    SHAPE ABUTMENT ;
    PORT
      LAYER M4 ;
      RECT 0.000 249.984 0.024 250.008 ;
    END
  END wd_in_A[21]
  PIN wd_in_B[21]
    DIRECTION INPUT ;
    USE SIGNAL ;
    SHAPE ABUTMENT ;
    PORT
      LAYER M4 ;
      RECT 46.906 249.984 46.930 250.008 ;
    END
  END wd_in_B[21]
  PIN wd_in_A[22]
    DIRECTION INPUT ;
    USE SIGNAL ;
    SHAPE ABUTMENT ;
    PORT
      LAYER M4 ;
      RECT 0.000 252.912 0.024 252.936 ;
    END
  END wd_in_A[22]
  PIN wd_in_B[22]
    DIRECTION INPUT ;
    USE SIGNAL ;
    SHAPE ABUTMENT ;
    PORT
      LAYER M4 ;
      RECT 46.906 252.912 46.930 252.936 ;
    END
  END wd_in_B[22]
  PIN wd_in_A[23]
    DIRECTION INPUT ;
    USE SIGNAL ;
    SHAPE ABUTMENT ;
    PORT
      LAYER M4 ;
      RECT 0.000 255.840 0.024 255.864 ;
    END
  END wd_in_A[23]
  PIN wd_in_B[23]
    DIRECTION INPUT ;
    USE SIGNAL ;
    SHAPE ABUTMENT ;
    PORT
      LAYER M4 ;
      RECT 46.906 255.840 46.930 255.864 ;
    END
  END wd_in_B[23]
  PIN wd_in_A[24]
    DIRECTION INPUT ;
    USE SIGNAL ;
    SHAPE ABUTMENT ;
    PORT
      LAYER M4 ;
      RECT 0.000 258.768 0.024 258.792 ;
    END
  END wd_in_A[24]
  PIN wd_in_B[24]
    DIRECTION INPUT ;
    USE SIGNAL ;
    SHAPE ABUTMENT ;
    PORT
      LAYER M4 ;
      RECT 46.906 258.768 46.930 258.792 ;
    END
  END wd_in_B[24]
  PIN wd_in_A[25]
    DIRECTION INPUT ;
    USE SIGNAL ;
    SHAPE ABUTMENT ;
    PORT
      LAYER M4 ;
      RECT 0.000 261.696 0.024 261.720 ;
    END
  END wd_in_A[25]
  PIN wd_in_B[25]
    DIRECTION INPUT ;
    USE SIGNAL ;
    SHAPE ABUTMENT ;
    PORT
      LAYER M4 ;
      RECT 46.906 261.696 46.930 261.720 ;
    END
  END wd_in_B[25]
  PIN wd_in_A[26]
    DIRECTION INPUT ;
    USE SIGNAL ;
    SHAPE ABUTMENT ;
    PORT
      LAYER M4 ;
      RECT 0.000 264.624 0.024 264.648 ;
    END
  END wd_in_A[26]
  PIN wd_in_B[26]
    DIRECTION INPUT ;
    USE SIGNAL ;
    SHAPE ABUTMENT ;
    PORT
      LAYER M4 ;
      RECT 46.906 264.624 46.930 264.648 ;
    END
  END wd_in_B[26]
  PIN wd_in_A[27]
    DIRECTION INPUT ;
    USE SIGNAL ;
    SHAPE ABUTMENT ;
    PORT
      LAYER M4 ;
      RECT 0.000 267.552 0.024 267.576 ;
    END
  END wd_in_A[27]
  PIN wd_in_B[27]
    DIRECTION INPUT ;
    USE SIGNAL ;
    SHAPE ABUTMENT ;
    PORT
      LAYER M4 ;
      RECT 46.906 267.552 46.930 267.576 ;
    END
  END wd_in_B[27]
  PIN wd_in_A[28]
    DIRECTION INPUT ;
    USE SIGNAL ;
    SHAPE ABUTMENT ;
    PORT
      LAYER M4 ;
      RECT 0.000 270.480 0.024 270.504 ;
    END
  END wd_in_A[28]
  PIN wd_in_B[28]
    DIRECTION INPUT ;
    USE SIGNAL ;
    SHAPE ABUTMENT ;
    PORT
      LAYER M4 ;
      RECT 46.906 270.480 46.930 270.504 ;
    END
  END wd_in_B[28]
  PIN wd_in_A[29]
    DIRECTION INPUT ;
    USE SIGNAL ;
    SHAPE ABUTMENT ;
    PORT
      LAYER M4 ;
      RECT 0.000 273.408 0.024 273.432 ;
    END
  END wd_in_A[29]
  PIN wd_in_B[29]
    DIRECTION INPUT ;
    USE SIGNAL ;
    SHAPE ABUTMENT ;
    PORT
      LAYER M4 ;
      RECT 46.906 273.408 46.930 273.432 ;
    END
  END wd_in_B[29]
  PIN wd_in_A[30]
    DIRECTION INPUT ;
    USE SIGNAL ;
    SHAPE ABUTMENT ;
    PORT
      LAYER M4 ;
      RECT 0.000 276.336 0.024 276.360 ;
    END
  END wd_in_A[30]
  PIN wd_in_B[30]
    DIRECTION INPUT ;
    USE SIGNAL ;
    SHAPE ABUTMENT ;
    PORT
      LAYER M4 ;
      RECT 46.906 276.336 46.930 276.360 ;
    END
  END wd_in_B[30]
  PIN wd_in_A[31]
    DIRECTION INPUT ;
    USE SIGNAL ;
    SHAPE ABUTMENT ;
    PORT
      LAYER M4 ;
      RECT 0.000 279.264 0.024 279.288 ;
    END
  END wd_in_A[31]
  PIN wd_in_B[31]
    DIRECTION INPUT ;
    USE SIGNAL ;
    SHAPE ABUTMENT ;
    PORT
      LAYER M4 ;
      RECT 46.906 279.264 46.930 279.288 ;
    END
  END wd_in_B[31]
  PIN addr_in_A[0]
    DIRECTION INPUT ;
    USE SIGNAL ;
    SHAPE ABUTMENT ;
    PORT
      LAYER M4 ;
      RECT 0.000 282.720 0.024 282.744 ;
    END
  END addr_in_A[0]
  PIN addr_in_B[0]
    DIRECTION INPUT ;
    USE SIGNAL ;
    SHAPE ABUTMENT ;
    PORT
      LAYER M4 ;
      RECT 46.906 282.720 46.930 282.744 ;
    END
  END addr_in_B[0]
  PIN addr_in_A[1]
    DIRECTION INPUT ;
    USE SIGNAL ;
    SHAPE ABUTMENT ;
    PORT
      LAYER M4 ;
      RECT 0.000 285.648 0.024 285.672 ;
    END
  END addr_in_A[1]
  PIN addr_in_B[1]
    DIRECTION INPUT ;
    USE SIGNAL ;
    SHAPE ABUTMENT ;
    PORT
      LAYER M4 ;
      RECT 46.906 285.648 46.930 285.672 ;
    END
  END addr_in_B[1]
  PIN addr_in_A[2]
    DIRECTION INPUT ;
    USE SIGNAL ;
    SHAPE ABUTMENT ;
    PORT
      LAYER M4 ;
      RECT 0.000 288.576 0.024 288.600 ;
    END
  END addr_in_A[2]
  PIN addr_in_B[2]
    DIRECTION INPUT ;
    USE SIGNAL ;
    SHAPE ABUTMENT ;
    PORT
      LAYER M4 ;
      RECT 46.906 288.576 46.930 288.600 ;
    END
  END addr_in_B[2]
  PIN addr_in_A[3]
    DIRECTION INPUT ;
    USE SIGNAL ;
    SHAPE ABUTMENT ;
    PORT
      LAYER M4 ;
      RECT 0.000 291.504 0.024 291.528 ;
    END
  END addr_in_A[3]
  PIN addr_in_B[3]
    DIRECTION INPUT ;
    USE SIGNAL ;
    SHAPE ABUTMENT ;
    PORT
      LAYER M4 ;
      RECT 46.906 291.504 46.930 291.528 ;
    END
  END addr_in_B[3]
  PIN addr_in_A[4]
    DIRECTION INPUT ;
    USE SIGNAL ;
    SHAPE ABUTMENT ;
    PORT
      LAYER M4 ;
      RECT 0.000 294.432 0.024 294.456 ;
    END
  END addr_in_A[4]
  PIN addr_in_B[4]
    DIRECTION INPUT ;
    USE SIGNAL ;
    SHAPE ABUTMENT ;
    PORT
      LAYER M4 ;
      RECT 46.906 294.432 46.930 294.456 ;
    END
  END addr_in_B[4]
  PIN addr_in_A[5]
    DIRECTION INPUT ;
    USE SIGNAL ;
    SHAPE ABUTMENT ;
    PORT
      LAYER M4 ;
      RECT 0.000 297.360 0.024 297.384 ;
    END
  END addr_in_A[5]
  PIN addr_in_B[5]
    DIRECTION INPUT ;
    USE SIGNAL ;
    SHAPE ABUTMENT ;
    PORT
      LAYER M4 ;
      RECT 46.906 297.360 46.930 297.384 ;
    END
  END addr_in_B[5]
  PIN addr_in_A[6]
    DIRECTION INPUT ;
    USE SIGNAL ;
    SHAPE ABUTMENT ;
    PORT
      LAYER M4 ;
      RECT 0.000 300.288 0.024 300.312 ;
    END
  END addr_in_A[6]
  PIN addr_in_B[6]
    DIRECTION INPUT ;
    USE SIGNAL ;
    SHAPE ABUTMENT ;
    PORT
      LAYER M4 ;
      RECT 46.906 300.288 46.930 300.312 ;
    END
  END addr_in_B[6]
  PIN addr_in_A[7]
    DIRECTION INPUT ;
    USE SIGNAL ;
    SHAPE ABUTMENT ;
    PORT
      LAYER M4 ;
      RECT 0.000 303.216 0.024 303.240 ;
    END
  END addr_in_A[7]
  PIN addr_in_B[7]
    DIRECTION INPUT ;
    USE SIGNAL ;
    SHAPE ABUTMENT ;
    PORT
      LAYER M4 ;
      RECT 46.906 303.216 46.930 303.240 ;
    END
  END addr_in_B[7]
  PIN addr_in_A[8]
    DIRECTION INPUT ;
    USE SIGNAL ;
    SHAPE ABUTMENT ;
    PORT
      LAYER M4 ;
      RECT 0.000 306.144 0.024 306.168 ;
    END
  END addr_in_A[8]
  PIN addr_in_B[8]
    DIRECTION INPUT ;
    USE SIGNAL ;
    SHAPE ABUTMENT ;
    PORT
      LAYER M4 ;
      RECT 46.906 306.144 46.930 306.168 ;
    END
  END addr_in_B[8]
  PIN addr_in_A[9]
    DIRECTION INPUT ;
    USE SIGNAL ;
    SHAPE ABUTMENT ;
    PORT
      LAYER M4 ;
      RECT 0.000 309.072 0.024 309.096 ;
    END
  END addr_in_A[9]
  PIN addr_in_B[9]
    DIRECTION INPUT ;
    USE SIGNAL ;
    SHAPE ABUTMENT ;
    PORT
      LAYER M4 ;
      RECT 46.906 309.072 46.930 309.096 ;
    END
  END addr_in_B[9]
  PIN addr_in_A[10]
    DIRECTION INPUT ;
    USE SIGNAL ;
    SHAPE ABUTMENT ;
    PORT
      LAYER M4 ;
      RECT 0.000 312.000 0.024 312.024 ;
    END
  END addr_in_A[10]
  PIN addr_in_B[10]
    DIRECTION INPUT ;
    USE SIGNAL ;
    SHAPE ABUTMENT ;
    PORT
      LAYER M4 ;
      RECT 46.906 312.000 46.930 312.024 ;
    END
  END addr_in_B[10]
  PIN addr_in_A[11]
    DIRECTION INPUT ;
    USE SIGNAL ;
    SHAPE ABUTMENT ;
    PORT
      LAYER M4 ;
      RECT 0.000 314.928 0.024 314.952 ;
    END
  END addr_in_A[11]
  PIN addr_in_B[11]
    DIRECTION INPUT ;
    USE SIGNAL ;
    SHAPE ABUTMENT ;
    PORT
      LAYER M4 ;
      RECT 46.906 314.928 46.930 314.952 ;
    END
  END addr_in_B[11]
  PIN addr_in_A[12]
    DIRECTION INPUT ;
    USE SIGNAL ;
    SHAPE ABUTMENT ;
    PORT
      LAYER M4 ;
      RECT 0.000 317.856 0.024 317.880 ;
    END
  END addr_in_A[12]
  PIN addr_in_B[12]
    DIRECTION INPUT ;
    USE SIGNAL ;
    SHAPE ABUTMENT ;
    PORT
      LAYER M4 ;
      RECT 46.906 317.856 46.930 317.880 ;
    END
  END addr_in_B[12]
  PIN addr_in_A[13]
    DIRECTION INPUT ;
    USE SIGNAL ;
    SHAPE ABUTMENT ;
    PORT
      LAYER M4 ;
      RECT 0.000 320.784 0.024 320.808 ;
    END
  END addr_in_A[13]
  PIN addr_in_B[13]
    DIRECTION INPUT ;
    USE SIGNAL ;
    SHAPE ABUTMENT ;
    PORT
      LAYER M4 ;
      RECT 46.906 320.784 46.930 320.808 ;
    END
  END addr_in_B[13]
  PIN we_in_A
    DIRECTION INPUT ;
    USE SIGNAL ;
    SHAPE ABUTMENT ;
    PORT
      LAYER M4 ;
      RECT 0.000 324.240 0.024 324.264 ;
    END
  END we_in_A
  PIN we_in_B
    DIRECTION INPUT ;
    USE SIGNAL ;
    SHAPE ABUTMENT ;
    PORT
      LAYER M4 ;
      RECT 46.906 324.240 46.930 324.264 ;
    END
  END we_in_B
  PIN ce_in
    DIRECTION INPUT ;
    USE SIGNAL ;
    SHAPE ABUTMENT ;
    PORT
      LAYER M4 ;
      RECT 0.000 327.168 0.024 327.192 ;
    END
  END ce_in
  PIN clk
    DIRECTION INPUT ;
    USE SIGNAL ;
    SHAPE ABUTMENT ;
    PORT
      LAYER M4 ;
      RECT 0.000 330.096 0.024 330.120 ;
    END
  END clk
  PIN VSS
    DIRECTION INOUT ;
    USE GROUND ;
    PORT
      LAYER M4 ;
      RECT 0.048 0.000 46.882 0.096 ;
      RECT 0.048 0.768 46.882 0.864 ;
      RECT 0.048 1.536 46.882 1.632 ;
      RECT 0.048 2.304 46.882 2.400 ;
      RECT 0.048 3.072 46.882 3.168 ;
      RECT 0.048 3.840 46.882 3.936 ;
      RECT 0.048 4.608 46.882 4.704 ;
      RECT 0.048 5.376 46.882 5.472 ;
      RECT 0.048 6.144 46.882 6.240 ;
      RECT 0.048 6.912 46.882 7.008 ;
      RECT 0.048 7.680 46.882 7.776 ;
      RECT 0.048 8.448 46.882 8.544 ;
      RECT 0.048 9.216 46.882 9.312 ;
      RECT 0.048 9.984 46.882 10.080 ;
      RECT 0.048 10.752 46.882 10.848 ;
      RECT 0.048 11.520 46.882 11.616 ;
      RECT 0.048 12.288 46.882 12.384 ;
      RECT 0.048 13.056 46.882 13.152 ;
      RECT 0.048 13.824 46.882 13.920 ;
      RECT 0.048 14.592 46.882 14.688 ;
      RECT 0.048 15.360 46.882 15.456 ;
      RECT 0.048 16.128 46.882 16.224 ;
      RECT 0.048 16.896 46.882 16.992 ;
      RECT 0.048 17.664 46.882 17.760 ;
      RECT 0.048 18.432 46.882 18.528 ;
      RECT 0.048 19.200 46.882 19.296 ;
      RECT 0.048 19.968 46.882 20.064 ;
      RECT 0.048 20.736 46.882 20.832 ;
      RECT 0.048 21.504 46.882 21.600 ;
      RECT 0.048 22.272 46.882 22.368 ;
      RECT 0.048 23.040 46.882 23.136 ;
      RECT 0.048 23.808 46.882 23.904 ;
      RECT 0.048 24.576 46.882 24.672 ;
      RECT 0.048 25.344 46.882 25.440 ;
      RECT 0.048 26.112 46.882 26.208 ;
      RECT 0.048 26.880 46.882 26.976 ;
      RECT 0.048 27.648 46.882 27.744 ;
      RECT 0.048 28.416 46.882 28.512 ;
      RECT 0.048 29.184 46.882 29.280 ;
      RECT 0.048 29.952 46.882 30.048 ;
      RECT 0.048 30.720 46.882 30.816 ;
      RECT 0.048 31.488 46.882 31.584 ;
      RECT 0.048 32.256 46.882 32.352 ;
      RECT 0.048 33.024 46.882 33.120 ;
      RECT 0.048 33.792 46.882 33.888 ;
      RECT 0.048 34.560 46.882 34.656 ;
      RECT 0.048 35.328 46.882 35.424 ;
      RECT 0.048 36.096 46.882 36.192 ;
      RECT 0.048 36.864 46.882 36.960 ;
      RECT 0.048 37.632 46.882 37.728 ;
      RECT 0.048 38.400 46.882 38.496 ;
      RECT 0.048 39.168 46.882 39.264 ;
      RECT 0.048 39.936 46.882 40.032 ;
      RECT 0.048 40.704 46.882 40.800 ;
      RECT 0.048 41.472 46.882 41.568 ;
      RECT 0.048 42.240 46.882 42.336 ;
      RECT 0.048 43.008 46.882 43.104 ;
      RECT 0.048 43.776 46.882 43.872 ;
      RECT 0.048 44.544 46.882 44.640 ;
      RECT 0.048 45.312 46.882 45.408 ;
      RECT 0.048 46.080 46.882 46.176 ;
      RECT 0.048 46.848 46.882 46.944 ;
      RECT 0.048 47.616 46.882 47.712 ;
      RECT 0.048 48.384 46.882 48.480 ;
      RECT 0.048 49.152 46.882 49.248 ;
      RECT 0.048 49.920 46.882 50.016 ;
      RECT 0.048 50.688 46.882 50.784 ;
      RECT 0.048 51.456 46.882 51.552 ;
      RECT 0.048 52.224 46.882 52.320 ;
      RECT 0.048 52.992 46.882 53.088 ;
      RECT 0.048 53.760 46.882 53.856 ;
      RECT 0.048 54.528 46.882 54.624 ;
      RECT 0.048 55.296 46.882 55.392 ;
      RECT 0.048 56.064 46.882 56.160 ;
      RECT 0.048 56.832 46.882 56.928 ;
      RECT 0.048 57.600 46.882 57.696 ;
      RECT 0.048 58.368 46.882 58.464 ;
      RECT 0.048 59.136 46.882 59.232 ;
      RECT 0.048 59.904 46.882 60.000 ;
      RECT 0.048 60.672 46.882 60.768 ;
      RECT 0.048 61.440 46.882 61.536 ;
      RECT 0.048 62.208 46.882 62.304 ;
      RECT 0.048 62.976 46.882 63.072 ;
      RECT 0.048 63.744 46.882 63.840 ;
      RECT 0.048 64.512 46.882 64.608 ;
      RECT 0.048 65.280 46.882 65.376 ;
      RECT 0.048 66.048 46.882 66.144 ;
      RECT 0.048 66.816 46.882 66.912 ;
      RECT 0.048 67.584 46.882 67.680 ;
      RECT 0.048 68.352 46.882 68.448 ;
      RECT 0.048 69.120 46.882 69.216 ;
      RECT 0.048 69.888 46.882 69.984 ;
      RECT 0.048 70.656 46.882 70.752 ;
      RECT 0.048 71.424 46.882 71.520 ;
      RECT 0.048 72.192 46.882 72.288 ;
      RECT 0.048 72.960 46.882 73.056 ;
      RECT 0.048 73.728 46.882 73.824 ;
      RECT 0.048 74.496 46.882 74.592 ;
      RECT 0.048 75.264 46.882 75.360 ;
      RECT 0.048 76.032 46.882 76.128 ;
      RECT 0.048 76.800 46.882 76.896 ;
      RECT 0.048 77.568 46.882 77.664 ;
      RECT 0.048 78.336 46.882 78.432 ;
      RECT 0.048 79.104 46.882 79.200 ;
      RECT 0.048 79.872 46.882 79.968 ;
      RECT 0.048 80.640 46.882 80.736 ;
      RECT 0.048 81.408 46.882 81.504 ;
      RECT 0.048 82.176 46.882 82.272 ;
      RECT 0.048 82.944 46.882 83.040 ;
      RECT 0.048 83.712 46.882 83.808 ;
      RECT 0.048 84.480 46.882 84.576 ;
      RECT 0.048 85.248 46.882 85.344 ;
      RECT 0.048 86.016 46.882 86.112 ;
      RECT 0.048 86.784 46.882 86.880 ;
      RECT 0.048 87.552 46.882 87.648 ;
      RECT 0.048 88.320 46.882 88.416 ;
      RECT 0.048 89.088 46.882 89.184 ;
      RECT 0.048 89.856 46.882 89.952 ;
      RECT 0.048 90.624 46.882 90.720 ;
      RECT 0.048 91.392 46.882 91.488 ;
      RECT 0.048 92.160 46.882 92.256 ;
      RECT 0.048 92.928 46.882 93.024 ;
      RECT 0.048 93.696 46.882 93.792 ;
      RECT 0.048 94.464 46.882 94.560 ;
      RECT 0.048 95.232 46.882 95.328 ;
      RECT 0.048 96.000 46.882 96.096 ;
      RECT 0.048 96.768 46.882 96.864 ;
      RECT 0.048 97.536 46.882 97.632 ;
      RECT 0.048 98.304 46.882 98.400 ;
      RECT 0.048 99.072 46.882 99.168 ;
      RECT 0.048 99.840 46.882 99.936 ;
      RECT 0.048 100.608 46.882 100.704 ;
      RECT 0.048 101.376 46.882 101.472 ;
      RECT 0.048 102.144 46.882 102.240 ;
      RECT 0.048 102.912 46.882 103.008 ;
      RECT 0.048 103.680 46.882 103.776 ;
      RECT 0.048 104.448 46.882 104.544 ;
      RECT 0.048 105.216 46.882 105.312 ;
      RECT 0.048 105.984 46.882 106.080 ;
      RECT 0.048 106.752 46.882 106.848 ;
      RECT 0.048 107.520 46.882 107.616 ;
      RECT 0.048 108.288 46.882 108.384 ;
      RECT 0.048 109.056 46.882 109.152 ;
      RECT 0.048 109.824 46.882 109.920 ;
      RECT 0.048 110.592 46.882 110.688 ;
      RECT 0.048 111.360 46.882 111.456 ;
      RECT 0.048 112.128 46.882 112.224 ;
      RECT 0.048 112.896 46.882 112.992 ;
      RECT 0.048 113.664 46.882 113.760 ;
      RECT 0.048 114.432 46.882 114.528 ;
      RECT 0.048 115.200 46.882 115.296 ;
      RECT 0.048 115.968 46.882 116.064 ;
      RECT 0.048 116.736 46.882 116.832 ;
      RECT 0.048 117.504 46.882 117.600 ;
      RECT 0.048 118.272 46.882 118.368 ;
      RECT 0.048 119.040 46.882 119.136 ;
      RECT 0.048 119.808 46.882 119.904 ;
      RECT 0.048 120.576 46.882 120.672 ;
      RECT 0.048 121.344 46.882 121.440 ;
      RECT 0.048 122.112 46.882 122.208 ;
      RECT 0.048 122.880 46.882 122.976 ;
      RECT 0.048 123.648 46.882 123.744 ;
      RECT 0.048 124.416 46.882 124.512 ;
      RECT 0.048 125.184 46.882 125.280 ;
      RECT 0.048 125.952 46.882 126.048 ;
      RECT 0.048 126.720 46.882 126.816 ;
      RECT 0.048 127.488 46.882 127.584 ;
      RECT 0.048 128.256 46.882 128.352 ;
      RECT 0.048 129.024 46.882 129.120 ;
      RECT 0.048 129.792 46.882 129.888 ;
      RECT 0.048 130.560 46.882 130.656 ;
      RECT 0.048 131.328 46.882 131.424 ;
      RECT 0.048 132.096 46.882 132.192 ;
      RECT 0.048 132.864 46.882 132.960 ;
      RECT 0.048 133.632 46.882 133.728 ;
      RECT 0.048 134.400 46.882 134.496 ;
      RECT 0.048 135.168 46.882 135.264 ;
      RECT 0.048 135.936 46.882 136.032 ;
      RECT 0.048 136.704 46.882 136.800 ;
      RECT 0.048 137.472 46.882 137.568 ;
      RECT 0.048 138.240 46.882 138.336 ;
      RECT 0.048 139.008 46.882 139.104 ;
      RECT 0.048 139.776 46.882 139.872 ;
      RECT 0.048 140.544 46.882 140.640 ;
      RECT 0.048 141.312 46.882 141.408 ;
      RECT 0.048 142.080 46.882 142.176 ;
      RECT 0.048 142.848 46.882 142.944 ;
      RECT 0.048 143.616 46.882 143.712 ;
      RECT 0.048 144.384 46.882 144.480 ;
      RECT 0.048 145.152 46.882 145.248 ;
      RECT 0.048 145.920 46.882 146.016 ;
      RECT 0.048 146.688 46.882 146.784 ;
      RECT 0.048 147.456 46.882 147.552 ;
      RECT 0.048 148.224 46.882 148.320 ;
      RECT 0.048 148.992 46.882 149.088 ;
      RECT 0.048 149.760 46.882 149.856 ;
      RECT 0.048 150.528 46.882 150.624 ;
      RECT 0.048 151.296 46.882 151.392 ;
      RECT 0.048 152.064 46.882 152.160 ;
      RECT 0.048 152.832 46.882 152.928 ;
      RECT 0.048 153.600 46.882 153.696 ;
      RECT 0.048 154.368 46.882 154.464 ;
      RECT 0.048 155.136 46.882 155.232 ;
      RECT 0.048 155.904 46.882 156.000 ;
      RECT 0.048 156.672 46.882 156.768 ;
      RECT 0.048 157.440 46.882 157.536 ;
      RECT 0.048 158.208 46.882 158.304 ;
      RECT 0.048 158.976 46.882 159.072 ;
      RECT 0.048 159.744 46.882 159.840 ;
      RECT 0.048 160.512 46.882 160.608 ;
      RECT 0.048 161.280 46.882 161.376 ;
      RECT 0.048 162.048 46.882 162.144 ;
      RECT 0.048 162.816 46.882 162.912 ;
      RECT 0.048 163.584 46.882 163.680 ;
      RECT 0.048 164.352 46.882 164.448 ;
      RECT 0.048 165.120 46.882 165.216 ;
      RECT 0.048 165.888 46.882 165.984 ;
      RECT 0.048 166.656 46.882 166.752 ;
      RECT 0.048 167.424 46.882 167.520 ;
      RECT 0.048 168.192 46.882 168.288 ;
      RECT 0.048 168.960 46.882 169.056 ;
      RECT 0.048 169.728 46.882 169.824 ;
      RECT 0.048 170.496 46.882 170.592 ;
      RECT 0.048 171.264 46.882 171.360 ;
      RECT 0.048 172.032 46.882 172.128 ;
      RECT 0.048 172.800 46.882 172.896 ;
      RECT 0.048 173.568 46.882 173.664 ;
      RECT 0.048 174.336 46.882 174.432 ;
      RECT 0.048 175.104 46.882 175.200 ;
      RECT 0.048 175.872 46.882 175.968 ;
      RECT 0.048 176.640 46.882 176.736 ;
      RECT 0.048 177.408 46.882 177.504 ;
      RECT 0.048 178.176 46.882 178.272 ;
      RECT 0.048 178.944 46.882 179.040 ;
      RECT 0.048 179.712 46.882 179.808 ;
      RECT 0.048 180.480 46.882 180.576 ;
      RECT 0.048 181.248 46.882 181.344 ;
      RECT 0.048 182.016 46.882 182.112 ;
      RECT 0.048 182.784 46.882 182.880 ;
      RECT 0.048 183.552 46.882 183.648 ;
      RECT 0.048 184.320 46.882 184.416 ;
      RECT 0.048 185.088 46.882 185.184 ;
      RECT 0.048 185.856 46.882 185.952 ;
      RECT 0.048 186.624 46.882 186.720 ;
      RECT 0.048 187.392 46.882 187.488 ;
      RECT 0.048 188.160 46.882 188.256 ;
      RECT 0.048 188.928 46.882 189.024 ;
      RECT 0.048 189.696 46.882 189.792 ;
      RECT 0.048 190.464 46.882 190.560 ;
      RECT 0.048 191.232 46.882 191.328 ;
      RECT 0.048 192.000 46.882 192.096 ;
      RECT 0.048 192.768 46.882 192.864 ;
      RECT 0.048 193.536 46.882 193.632 ;
      RECT 0.048 194.304 46.882 194.400 ;
      RECT 0.048 195.072 46.882 195.168 ;
      RECT 0.048 195.840 46.882 195.936 ;
      RECT 0.048 196.608 46.882 196.704 ;
      RECT 0.048 197.376 46.882 197.472 ;
      RECT 0.048 198.144 46.882 198.240 ;
      RECT 0.048 198.912 46.882 199.008 ;
      RECT 0.048 199.680 46.882 199.776 ;
      RECT 0.048 200.448 46.882 200.544 ;
      RECT 0.048 201.216 46.882 201.312 ;
      RECT 0.048 201.984 46.882 202.080 ;
      RECT 0.048 202.752 46.882 202.848 ;
      RECT 0.048 203.520 46.882 203.616 ;
      RECT 0.048 204.288 46.882 204.384 ;
      RECT 0.048 205.056 46.882 205.152 ;
      RECT 0.048 205.824 46.882 205.920 ;
      RECT 0.048 206.592 46.882 206.688 ;
      RECT 0.048 207.360 46.882 207.456 ;
      RECT 0.048 208.128 46.882 208.224 ;
      RECT 0.048 208.896 46.882 208.992 ;
      RECT 0.048 209.664 46.882 209.760 ;
      RECT 0.048 210.432 46.882 210.528 ;
      RECT 0.048 211.200 46.882 211.296 ;
      RECT 0.048 211.968 46.882 212.064 ;
      RECT 0.048 212.736 46.882 212.832 ;
      RECT 0.048 213.504 46.882 213.600 ;
      RECT 0.048 214.272 46.882 214.368 ;
      RECT 0.048 215.040 46.882 215.136 ;
      RECT 0.048 215.808 46.882 215.904 ;
      RECT 0.048 216.576 46.882 216.672 ;
      RECT 0.048 217.344 46.882 217.440 ;
      RECT 0.048 218.112 46.882 218.208 ;
      RECT 0.048 218.880 46.882 218.976 ;
      RECT 0.048 219.648 46.882 219.744 ;
      RECT 0.048 220.416 46.882 220.512 ;
      RECT 0.048 221.184 46.882 221.280 ;
      RECT 0.048 221.952 46.882 222.048 ;
      RECT 0.048 222.720 46.882 222.816 ;
      RECT 0.048 223.488 46.882 223.584 ;
      RECT 0.048 224.256 46.882 224.352 ;
      RECT 0.048 225.024 46.882 225.120 ;
      RECT 0.048 225.792 46.882 225.888 ;
      RECT 0.048 226.560 46.882 226.656 ;
      RECT 0.048 227.328 46.882 227.424 ;
      RECT 0.048 228.096 46.882 228.192 ;
      RECT 0.048 228.864 46.882 228.960 ;
      RECT 0.048 229.632 46.882 229.728 ;
      RECT 0.048 230.400 46.882 230.496 ;
      RECT 0.048 231.168 46.882 231.264 ;
      RECT 0.048 231.936 46.882 232.032 ;
      RECT 0.048 232.704 46.882 232.800 ;
      RECT 0.048 233.472 46.882 233.568 ;
      RECT 0.048 234.240 46.882 234.336 ;
      RECT 0.048 235.008 46.882 235.104 ;
      RECT 0.048 235.776 46.882 235.872 ;
      RECT 0.048 236.544 46.882 236.640 ;
      RECT 0.048 237.312 46.882 237.408 ;
      RECT 0.048 238.080 46.882 238.176 ;
      RECT 0.048 238.848 46.882 238.944 ;
      RECT 0.048 239.616 46.882 239.712 ;
      RECT 0.048 240.384 46.882 240.480 ;
      RECT 0.048 241.152 46.882 241.248 ;
      RECT 0.048 241.920 46.882 242.016 ;
      RECT 0.048 242.688 46.882 242.784 ;
      RECT 0.048 243.456 46.882 243.552 ;
      RECT 0.048 244.224 46.882 244.320 ;
      RECT 0.048 244.992 46.882 245.088 ;
      RECT 0.048 245.760 46.882 245.856 ;
      RECT 0.048 246.528 46.882 246.624 ;
      RECT 0.048 247.296 46.882 247.392 ;
      RECT 0.048 248.064 46.882 248.160 ;
      RECT 0.048 248.832 46.882 248.928 ;
      RECT 0.048 249.600 46.882 249.696 ;
      RECT 0.048 250.368 46.882 250.464 ;
      RECT 0.048 251.136 46.882 251.232 ;
      RECT 0.048 251.904 46.882 252.000 ;
      RECT 0.048 252.672 46.882 252.768 ;
      RECT 0.048 253.440 46.882 253.536 ;
      RECT 0.048 254.208 46.882 254.304 ;
      RECT 0.048 254.976 46.882 255.072 ;
      RECT 0.048 255.744 46.882 255.840 ;
      RECT 0.048 256.512 46.882 256.608 ;
      RECT 0.048 257.280 46.882 257.376 ;
      RECT 0.048 258.048 46.882 258.144 ;
      RECT 0.048 258.816 46.882 258.912 ;
      RECT 0.048 259.584 46.882 259.680 ;
      RECT 0.048 260.352 46.882 260.448 ;
      RECT 0.048 261.120 46.882 261.216 ;
      RECT 0.048 261.888 46.882 261.984 ;
      RECT 0.048 262.656 46.882 262.752 ;
      RECT 0.048 263.424 46.882 263.520 ;
      RECT 0.048 264.192 46.882 264.288 ;
      RECT 0.048 264.960 46.882 265.056 ;
      RECT 0.048 265.728 46.882 265.824 ;
      RECT 0.048 266.496 46.882 266.592 ;
      RECT 0.048 267.264 46.882 267.360 ;
      RECT 0.048 268.032 46.882 268.128 ;
      RECT 0.048 268.800 46.882 268.896 ;
      RECT 0.048 269.568 46.882 269.664 ;
      RECT 0.048 270.336 46.882 270.432 ;
      RECT 0.048 271.104 46.882 271.200 ;
      RECT 0.048 271.872 46.882 271.968 ;
      RECT 0.048 272.640 46.882 272.736 ;
      RECT 0.048 273.408 46.882 273.504 ;
      RECT 0.048 274.176 46.882 274.272 ;
      RECT 0.048 274.944 46.882 275.040 ;
      RECT 0.048 275.712 46.882 275.808 ;
      RECT 0.048 276.480 46.882 276.576 ;
      RECT 0.048 277.248 46.882 277.344 ;
      RECT 0.048 278.016 46.882 278.112 ;
      RECT 0.048 278.784 46.882 278.880 ;
      RECT 0.048 279.552 46.882 279.648 ;
      RECT 0.048 280.320 46.882 280.416 ;
      RECT 0.048 281.088 46.882 281.184 ;
      RECT 0.048 281.856 46.882 281.952 ;
      RECT 0.048 282.624 46.882 282.720 ;
      RECT 0.048 283.392 46.882 283.488 ;
      RECT 0.048 284.160 46.882 284.256 ;
      RECT 0.048 284.928 46.882 285.024 ;
      RECT 0.048 285.696 46.882 285.792 ;
      RECT 0.048 286.464 46.882 286.560 ;
      RECT 0.048 287.232 46.882 287.328 ;
      RECT 0.048 288.000 46.882 288.096 ;
      RECT 0.048 288.768 46.882 288.864 ;
      RECT 0.048 289.536 46.882 289.632 ;
      RECT 0.048 290.304 46.882 290.400 ;
      RECT 0.048 291.072 46.882 291.168 ;
      RECT 0.048 291.840 46.882 291.936 ;
      RECT 0.048 292.608 46.882 292.704 ;
      RECT 0.048 293.376 46.882 293.472 ;
      RECT 0.048 294.144 46.882 294.240 ;
      RECT 0.048 294.912 46.882 295.008 ;
      RECT 0.048 295.680 46.882 295.776 ;
      RECT 0.048 296.448 46.882 296.544 ;
      RECT 0.048 297.216 46.882 297.312 ;
      RECT 0.048 297.984 46.882 298.080 ;
      RECT 0.048 298.752 46.882 298.848 ;
      RECT 0.048 299.520 46.882 299.616 ;
      RECT 0.048 300.288 46.882 300.384 ;
      RECT 0.048 301.056 46.882 301.152 ;
      RECT 0.048 301.824 46.882 301.920 ;
      RECT 0.048 302.592 46.882 302.688 ;
      RECT 0.048 303.360 46.882 303.456 ;
      RECT 0.048 304.128 46.882 304.224 ;
      RECT 0.048 304.896 46.882 304.992 ;
      RECT 0.048 305.664 46.882 305.760 ;
      RECT 0.048 306.432 46.882 306.528 ;
      RECT 0.048 307.200 46.882 307.296 ;
      RECT 0.048 307.968 46.882 308.064 ;
      RECT 0.048 308.736 46.882 308.832 ;
      RECT 0.048 309.504 46.882 309.600 ;
      RECT 0.048 310.272 46.882 310.368 ;
      RECT 0.048 311.040 46.882 311.136 ;
      RECT 0.048 311.808 46.882 311.904 ;
      RECT 0.048 312.576 46.882 312.672 ;
      RECT 0.048 313.344 46.882 313.440 ;
      RECT 0.048 314.112 46.882 314.208 ;
      RECT 0.048 314.880 46.882 314.976 ;
      RECT 0.048 315.648 46.882 315.744 ;
      RECT 0.048 316.416 46.882 316.512 ;
      RECT 0.048 317.184 46.882 317.280 ;
      RECT 0.048 317.952 46.882 318.048 ;
      RECT 0.048 318.720 46.882 318.816 ;
      RECT 0.048 319.488 46.882 319.584 ;
      RECT 0.048 320.256 46.882 320.352 ;
      RECT 0.048 321.024 46.882 321.120 ;
      RECT 0.048 321.792 46.882 321.888 ;
      RECT 0.048 322.560 46.882 322.656 ;
      RECT 0.048 323.328 46.882 323.424 ;
      RECT 0.048 324.096 46.882 324.192 ;
      RECT 0.048 324.864 46.882 324.960 ;
      RECT 0.048 325.632 46.882 325.728 ;
      RECT 0.048 326.400 46.882 326.496 ;
      RECT 0.048 327.168 46.882 327.264 ;
      RECT 0.048 327.936 46.882 328.032 ;
      RECT 0.048 328.704 46.882 328.800 ;
      RECT 0.048 329.472 46.882 329.568 ;
      RECT 0.048 330.240 46.882 330.336 ;
      RECT 0.048 331.008 46.882 331.104 ;
      RECT 0.048 331.776 46.882 331.872 ;
      RECT 0.048 332.544 46.882 332.640 ;
    END
  END VSS
  PIN VDD
    DIRECTION INOUT ;
    USE POWER ;
    PORT
      LAYER M4 ;
      RECT 0.048 0.384 46.882 0.480 ;
      RECT 0.048 1.152 46.882 1.248 ;
      RECT 0.048 1.920 46.882 2.016 ;
      RECT 0.048 2.688 46.882 2.784 ;
      RECT 0.048 3.456 46.882 3.552 ;
      RECT 0.048 4.224 46.882 4.320 ;
      RECT 0.048 4.992 46.882 5.088 ;
      RECT 0.048 5.760 46.882 5.856 ;
      RECT 0.048 6.528 46.882 6.624 ;
      RECT 0.048 7.296 46.882 7.392 ;
      RECT 0.048 8.064 46.882 8.160 ;
      RECT 0.048 8.832 46.882 8.928 ;
      RECT 0.048 9.600 46.882 9.696 ;
      RECT 0.048 10.368 46.882 10.464 ;
      RECT 0.048 11.136 46.882 11.232 ;
      RECT 0.048 11.904 46.882 12.000 ;
      RECT 0.048 12.672 46.882 12.768 ;
      RECT 0.048 13.440 46.882 13.536 ;
      RECT 0.048 14.208 46.882 14.304 ;
      RECT 0.048 14.976 46.882 15.072 ;
      RECT 0.048 15.744 46.882 15.840 ;
      RECT 0.048 16.512 46.882 16.608 ;
      RECT 0.048 17.280 46.882 17.376 ;
      RECT 0.048 18.048 46.882 18.144 ;
      RECT 0.048 18.816 46.882 18.912 ;
      RECT 0.048 19.584 46.882 19.680 ;
      RECT 0.048 20.352 46.882 20.448 ;
      RECT 0.048 21.120 46.882 21.216 ;
      RECT 0.048 21.888 46.882 21.984 ;
      RECT 0.048 22.656 46.882 22.752 ;
      RECT 0.048 23.424 46.882 23.520 ;
      RECT 0.048 24.192 46.882 24.288 ;
      RECT 0.048 24.960 46.882 25.056 ;
      RECT 0.048 25.728 46.882 25.824 ;
      RECT 0.048 26.496 46.882 26.592 ;
      RECT 0.048 27.264 46.882 27.360 ;
      RECT 0.048 28.032 46.882 28.128 ;
      RECT 0.048 28.800 46.882 28.896 ;
      RECT 0.048 29.568 46.882 29.664 ;
      RECT 0.048 30.336 46.882 30.432 ;
      RECT 0.048 31.104 46.882 31.200 ;
      RECT 0.048 31.872 46.882 31.968 ;
      RECT 0.048 32.640 46.882 32.736 ;
      RECT 0.048 33.408 46.882 33.504 ;
      RECT 0.048 34.176 46.882 34.272 ;
      RECT 0.048 34.944 46.882 35.040 ;
      RECT 0.048 35.712 46.882 35.808 ;
      RECT 0.048 36.480 46.882 36.576 ;
      RECT 0.048 37.248 46.882 37.344 ;
      RECT 0.048 38.016 46.882 38.112 ;
      RECT 0.048 38.784 46.882 38.880 ;
      RECT 0.048 39.552 46.882 39.648 ;
      RECT 0.048 40.320 46.882 40.416 ;
      RECT 0.048 41.088 46.882 41.184 ;
      RECT 0.048 41.856 46.882 41.952 ;
      RECT 0.048 42.624 46.882 42.720 ;
      RECT 0.048 43.392 46.882 43.488 ;
      RECT 0.048 44.160 46.882 44.256 ;
      RECT 0.048 44.928 46.882 45.024 ;
      RECT 0.048 45.696 46.882 45.792 ;
      RECT 0.048 46.464 46.882 46.560 ;
      RECT 0.048 47.232 46.882 47.328 ;
      RECT 0.048 48.000 46.882 48.096 ;
      RECT 0.048 48.768 46.882 48.864 ;
      RECT 0.048 49.536 46.882 49.632 ;
      RECT 0.048 50.304 46.882 50.400 ;
      RECT 0.048 51.072 46.882 51.168 ;
      RECT 0.048 51.840 46.882 51.936 ;
      RECT 0.048 52.608 46.882 52.704 ;
      RECT 0.048 53.376 46.882 53.472 ;
      RECT 0.048 54.144 46.882 54.240 ;
      RECT 0.048 54.912 46.882 55.008 ;
      RECT 0.048 55.680 46.882 55.776 ;
      RECT 0.048 56.448 46.882 56.544 ;
      RECT 0.048 57.216 46.882 57.312 ;
      RECT 0.048 57.984 46.882 58.080 ;
      RECT 0.048 58.752 46.882 58.848 ;
      RECT 0.048 59.520 46.882 59.616 ;
      RECT 0.048 60.288 46.882 60.384 ;
      RECT 0.048 61.056 46.882 61.152 ;
      RECT 0.048 61.824 46.882 61.920 ;
      RECT 0.048 62.592 46.882 62.688 ;
      RECT 0.048 63.360 46.882 63.456 ;
      RECT 0.048 64.128 46.882 64.224 ;
      RECT 0.048 64.896 46.882 64.992 ;
      RECT 0.048 65.664 46.882 65.760 ;
      RECT 0.048 66.432 46.882 66.528 ;
      RECT 0.048 67.200 46.882 67.296 ;
      RECT 0.048 67.968 46.882 68.064 ;
      RECT 0.048 68.736 46.882 68.832 ;
      RECT 0.048 69.504 46.882 69.600 ;
      RECT 0.048 70.272 46.882 70.368 ;
      RECT 0.048 71.040 46.882 71.136 ;
      RECT 0.048 71.808 46.882 71.904 ;
      RECT 0.048 72.576 46.882 72.672 ;
      RECT 0.048 73.344 46.882 73.440 ;
      RECT 0.048 74.112 46.882 74.208 ;
      RECT 0.048 74.880 46.882 74.976 ;
      RECT 0.048 75.648 46.882 75.744 ;
      RECT 0.048 76.416 46.882 76.512 ;
      RECT 0.048 77.184 46.882 77.280 ;
      RECT 0.048 77.952 46.882 78.048 ;
      RECT 0.048 78.720 46.882 78.816 ;
      RECT 0.048 79.488 46.882 79.584 ;
      RECT 0.048 80.256 46.882 80.352 ;
      RECT 0.048 81.024 46.882 81.120 ;
      RECT 0.048 81.792 46.882 81.888 ;
      RECT 0.048 82.560 46.882 82.656 ;
      RECT 0.048 83.328 46.882 83.424 ;
      RECT 0.048 84.096 46.882 84.192 ;
      RECT 0.048 84.864 46.882 84.960 ;
      RECT 0.048 85.632 46.882 85.728 ;
      RECT 0.048 86.400 46.882 86.496 ;
      RECT 0.048 87.168 46.882 87.264 ;
      RECT 0.048 87.936 46.882 88.032 ;
      RECT 0.048 88.704 46.882 88.800 ;
      RECT 0.048 89.472 46.882 89.568 ;
      RECT 0.048 90.240 46.882 90.336 ;
      RECT 0.048 91.008 46.882 91.104 ;
      RECT 0.048 91.776 46.882 91.872 ;
      RECT 0.048 92.544 46.882 92.640 ;
      RECT 0.048 93.312 46.882 93.408 ;
      RECT 0.048 94.080 46.882 94.176 ;
      RECT 0.048 94.848 46.882 94.944 ;
      RECT 0.048 95.616 46.882 95.712 ;
      RECT 0.048 96.384 46.882 96.480 ;
      RECT 0.048 97.152 46.882 97.248 ;
      RECT 0.048 97.920 46.882 98.016 ;
      RECT 0.048 98.688 46.882 98.784 ;
      RECT 0.048 99.456 46.882 99.552 ;
      RECT 0.048 100.224 46.882 100.320 ;
      RECT 0.048 100.992 46.882 101.088 ;
      RECT 0.048 101.760 46.882 101.856 ;
      RECT 0.048 102.528 46.882 102.624 ;
      RECT 0.048 103.296 46.882 103.392 ;
      RECT 0.048 104.064 46.882 104.160 ;
      RECT 0.048 104.832 46.882 104.928 ;
      RECT 0.048 105.600 46.882 105.696 ;
      RECT 0.048 106.368 46.882 106.464 ;
      RECT 0.048 107.136 46.882 107.232 ;
      RECT 0.048 107.904 46.882 108.000 ;
      RECT 0.048 108.672 46.882 108.768 ;
      RECT 0.048 109.440 46.882 109.536 ;
      RECT 0.048 110.208 46.882 110.304 ;
      RECT 0.048 110.976 46.882 111.072 ;
      RECT 0.048 111.744 46.882 111.840 ;
      RECT 0.048 112.512 46.882 112.608 ;
      RECT 0.048 113.280 46.882 113.376 ;
      RECT 0.048 114.048 46.882 114.144 ;
      RECT 0.048 114.816 46.882 114.912 ;
      RECT 0.048 115.584 46.882 115.680 ;
      RECT 0.048 116.352 46.882 116.448 ;
      RECT 0.048 117.120 46.882 117.216 ;
      RECT 0.048 117.888 46.882 117.984 ;
      RECT 0.048 118.656 46.882 118.752 ;
      RECT 0.048 119.424 46.882 119.520 ;
      RECT 0.048 120.192 46.882 120.288 ;
      RECT 0.048 120.960 46.882 121.056 ;
      RECT 0.048 121.728 46.882 121.824 ;
      RECT 0.048 122.496 46.882 122.592 ;
      RECT 0.048 123.264 46.882 123.360 ;
      RECT 0.048 124.032 46.882 124.128 ;
      RECT 0.048 124.800 46.882 124.896 ;
      RECT 0.048 125.568 46.882 125.664 ;
      RECT 0.048 126.336 46.882 126.432 ;
      RECT 0.048 127.104 46.882 127.200 ;
      RECT 0.048 127.872 46.882 127.968 ;
      RECT 0.048 128.640 46.882 128.736 ;
      RECT 0.048 129.408 46.882 129.504 ;
      RECT 0.048 130.176 46.882 130.272 ;
      RECT 0.048 130.944 46.882 131.040 ;
      RECT 0.048 131.712 46.882 131.808 ;
      RECT 0.048 132.480 46.882 132.576 ;
      RECT 0.048 133.248 46.882 133.344 ;
      RECT 0.048 134.016 46.882 134.112 ;
      RECT 0.048 134.784 46.882 134.880 ;
      RECT 0.048 135.552 46.882 135.648 ;
      RECT 0.048 136.320 46.882 136.416 ;
      RECT 0.048 137.088 46.882 137.184 ;
      RECT 0.048 137.856 46.882 137.952 ;
      RECT 0.048 138.624 46.882 138.720 ;
      RECT 0.048 139.392 46.882 139.488 ;
      RECT 0.048 140.160 46.882 140.256 ;
      RECT 0.048 140.928 46.882 141.024 ;
      RECT 0.048 141.696 46.882 141.792 ;
      RECT 0.048 142.464 46.882 142.560 ;
      RECT 0.048 143.232 46.882 143.328 ;
      RECT 0.048 144.000 46.882 144.096 ;
      RECT 0.048 144.768 46.882 144.864 ;
      RECT 0.048 145.536 46.882 145.632 ;
      RECT 0.048 146.304 46.882 146.400 ;
      RECT 0.048 147.072 46.882 147.168 ;
      RECT 0.048 147.840 46.882 147.936 ;
      RECT 0.048 148.608 46.882 148.704 ;
      RECT 0.048 149.376 46.882 149.472 ;
      RECT 0.048 150.144 46.882 150.240 ;
      RECT 0.048 150.912 46.882 151.008 ;
      RECT 0.048 151.680 46.882 151.776 ;
      RECT 0.048 152.448 46.882 152.544 ;
      RECT 0.048 153.216 46.882 153.312 ;
      RECT 0.048 153.984 46.882 154.080 ;
      RECT 0.048 154.752 46.882 154.848 ;
      RECT 0.048 155.520 46.882 155.616 ;
      RECT 0.048 156.288 46.882 156.384 ;
      RECT 0.048 157.056 46.882 157.152 ;
      RECT 0.048 157.824 46.882 157.920 ;
      RECT 0.048 158.592 46.882 158.688 ;
      RECT 0.048 159.360 46.882 159.456 ;
      RECT 0.048 160.128 46.882 160.224 ;
      RECT 0.048 160.896 46.882 160.992 ;
      RECT 0.048 161.664 46.882 161.760 ;
      RECT 0.048 162.432 46.882 162.528 ;
      RECT 0.048 163.200 46.882 163.296 ;
      RECT 0.048 163.968 46.882 164.064 ;
      RECT 0.048 164.736 46.882 164.832 ;
      RECT 0.048 165.504 46.882 165.600 ;
      RECT 0.048 166.272 46.882 166.368 ;
      RECT 0.048 167.040 46.882 167.136 ;
      RECT 0.048 167.808 46.882 167.904 ;
      RECT 0.048 168.576 46.882 168.672 ;
      RECT 0.048 169.344 46.882 169.440 ;
      RECT 0.048 170.112 46.882 170.208 ;
      RECT 0.048 170.880 46.882 170.976 ;
      RECT 0.048 171.648 46.882 171.744 ;
      RECT 0.048 172.416 46.882 172.512 ;
      RECT 0.048 173.184 46.882 173.280 ;
      RECT 0.048 173.952 46.882 174.048 ;
      RECT 0.048 174.720 46.882 174.816 ;
      RECT 0.048 175.488 46.882 175.584 ;
      RECT 0.048 176.256 46.882 176.352 ;
      RECT 0.048 177.024 46.882 177.120 ;
      RECT 0.048 177.792 46.882 177.888 ;
      RECT 0.048 178.560 46.882 178.656 ;
      RECT 0.048 179.328 46.882 179.424 ;
      RECT 0.048 180.096 46.882 180.192 ;
      RECT 0.048 180.864 46.882 180.960 ;
      RECT 0.048 181.632 46.882 181.728 ;
      RECT 0.048 182.400 46.882 182.496 ;
      RECT 0.048 183.168 46.882 183.264 ;
      RECT 0.048 183.936 46.882 184.032 ;
      RECT 0.048 184.704 46.882 184.800 ;
      RECT 0.048 185.472 46.882 185.568 ;
      RECT 0.048 186.240 46.882 186.336 ;
      RECT 0.048 187.008 46.882 187.104 ;
      RECT 0.048 187.776 46.882 187.872 ;
      RECT 0.048 188.544 46.882 188.640 ;
      RECT 0.048 189.312 46.882 189.408 ;
      RECT 0.048 190.080 46.882 190.176 ;
      RECT 0.048 190.848 46.882 190.944 ;
      RECT 0.048 191.616 46.882 191.712 ;
      RECT 0.048 192.384 46.882 192.480 ;
      RECT 0.048 193.152 46.882 193.248 ;
      RECT 0.048 193.920 46.882 194.016 ;
      RECT 0.048 194.688 46.882 194.784 ;
      RECT 0.048 195.456 46.882 195.552 ;
      RECT 0.048 196.224 46.882 196.320 ;
      RECT 0.048 196.992 46.882 197.088 ;
      RECT 0.048 197.760 46.882 197.856 ;
      RECT 0.048 198.528 46.882 198.624 ;
      RECT 0.048 199.296 46.882 199.392 ;
      RECT 0.048 200.064 46.882 200.160 ;
      RECT 0.048 200.832 46.882 200.928 ;
      RECT 0.048 201.600 46.882 201.696 ;
      RECT 0.048 202.368 46.882 202.464 ;
      RECT 0.048 203.136 46.882 203.232 ;
      RECT 0.048 203.904 46.882 204.000 ;
      RECT 0.048 204.672 46.882 204.768 ;
      RECT 0.048 205.440 46.882 205.536 ;
      RECT 0.048 206.208 46.882 206.304 ;
      RECT 0.048 206.976 46.882 207.072 ;
      RECT 0.048 207.744 46.882 207.840 ;
      RECT 0.048 208.512 46.882 208.608 ;
      RECT 0.048 209.280 46.882 209.376 ;
      RECT 0.048 210.048 46.882 210.144 ;
      RECT 0.048 210.816 46.882 210.912 ;
      RECT 0.048 211.584 46.882 211.680 ;
      RECT 0.048 212.352 46.882 212.448 ;
      RECT 0.048 213.120 46.882 213.216 ;
      RECT 0.048 213.888 46.882 213.984 ;
      RECT 0.048 214.656 46.882 214.752 ;
      RECT 0.048 215.424 46.882 215.520 ;
      RECT 0.048 216.192 46.882 216.288 ;
      RECT 0.048 216.960 46.882 217.056 ;
      RECT 0.048 217.728 46.882 217.824 ;
      RECT 0.048 218.496 46.882 218.592 ;
      RECT 0.048 219.264 46.882 219.360 ;
      RECT 0.048 220.032 46.882 220.128 ;
      RECT 0.048 220.800 46.882 220.896 ;
      RECT 0.048 221.568 46.882 221.664 ;
      RECT 0.048 222.336 46.882 222.432 ;
      RECT 0.048 223.104 46.882 223.200 ;
      RECT 0.048 223.872 46.882 223.968 ;
      RECT 0.048 224.640 46.882 224.736 ;
      RECT 0.048 225.408 46.882 225.504 ;
      RECT 0.048 226.176 46.882 226.272 ;
      RECT 0.048 226.944 46.882 227.040 ;
      RECT 0.048 227.712 46.882 227.808 ;
      RECT 0.048 228.480 46.882 228.576 ;
      RECT 0.048 229.248 46.882 229.344 ;
      RECT 0.048 230.016 46.882 230.112 ;
      RECT 0.048 230.784 46.882 230.880 ;
      RECT 0.048 231.552 46.882 231.648 ;
      RECT 0.048 232.320 46.882 232.416 ;
      RECT 0.048 233.088 46.882 233.184 ;
      RECT 0.048 233.856 46.882 233.952 ;
      RECT 0.048 234.624 46.882 234.720 ;
      RECT 0.048 235.392 46.882 235.488 ;
      RECT 0.048 236.160 46.882 236.256 ;
      RECT 0.048 236.928 46.882 237.024 ;
      RECT 0.048 237.696 46.882 237.792 ;
      RECT 0.048 238.464 46.882 238.560 ;
      RECT 0.048 239.232 46.882 239.328 ;
      RECT 0.048 240.000 46.882 240.096 ;
      RECT 0.048 240.768 46.882 240.864 ;
      RECT 0.048 241.536 46.882 241.632 ;
      RECT 0.048 242.304 46.882 242.400 ;
      RECT 0.048 243.072 46.882 243.168 ;
      RECT 0.048 243.840 46.882 243.936 ;
      RECT 0.048 244.608 46.882 244.704 ;
      RECT 0.048 245.376 46.882 245.472 ;
      RECT 0.048 246.144 46.882 246.240 ;
      RECT 0.048 246.912 46.882 247.008 ;
      RECT 0.048 247.680 46.882 247.776 ;
      RECT 0.048 248.448 46.882 248.544 ;
      RECT 0.048 249.216 46.882 249.312 ;
      RECT 0.048 249.984 46.882 250.080 ;
      RECT 0.048 250.752 46.882 250.848 ;
      RECT 0.048 251.520 46.882 251.616 ;
      RECT 0.048 252.288 46.882 252.384 ;
      RECT 0.048 253.056 46.882 253.152 ;
      RECT 0.048 253.824 46.882 253.920 ;
      RECT 0.048 254.592 46.882 254.688 ;
      RECT 0.048 255.360 46.882 255.456 ;
      RECT 0.048 256.128 46.882 256.224 ;
      RECT 0.048 256.896 46.882 256.992 ;
      RECT 0.048 257.664 46.882 257.760 ;
      RECT 0.048 258.432 46.882 258.528 ;
      RECT 0.048 259.200 46.882 259.296 ;
      RECT 0.048 259.968 46.882 260.064 ;
      RECT 0.048 260.736 46.882 260.832 ;
      RECT 0.048 261.504 46.882 261.600 ;
      RECT 0.048 262.272 46.882 262.368 ;
      RECT 0.048 263.040 46.882 263.136 ;
      RECT 0.048 263.808 46.882 263.904 ;
      RECT 0.048 264.576 46.882 264.672 ;
      RECT 0.048 265.344 46.882 265.440 ;
      RECT 0.048 266.112 46.882 266.208 ;
      RECT 0.048 266.880 46.882 266.976 ;
      RECT 0.048 267.648 46.882 267.744 ;
      RECT 0.048 268.416 46.882 268.512 ;
      RECT 0.048 269.184 46.882 269.280 ;
      RECT 0.048 269.952 46.882 270.048 ;
      RECT 0.048 270.720 46.882 270.816 ;
      RECT 0.048 271.488 46.882 271.584 ;
      RECT 0.048 272.256 46.882 272.352 ;
      RECT 0.048 273.024 46.882 273.120 ;
      RECT 0.048 273.792 46.882 273.888 ;
      RECT 0.048 274.560 46.882 274.656 ;
      RECT 0.048 275.328 46.882 275.424 ;
      RECT 0.048 276.096 46.882 276.192 ;
      RECT 0.048 276.864 46.882 276.960 ;
      RECT 0.048 277.632 46.882 277.728 ;
      RECT 0.048 278.400 46.882 278.496 ;
      RECT 0.048 279.168 46.882 279.264 ;
      RECT 0.048 279.936 46.882 280.032 ;
      RECT 0.048 280.704 46.882 280.800 ;
      RECT 0.048 281.472 46.882 281.568 ;
      RECT 0.048 282.240 46.882 282.336 ;
      RECT 0.048 283.008 46.882 283.104 ;
      RECT 0.048 283.776 46.882 283.872 ;
      RECT 0.048 284.544 46.882 284.640 ;
      RECT 0.048 285.312 46.882 285.408 ;
      RECT 0.048 286.080 46.882 286.176 ;
      RECT 0.048 286.848 46.882 286.944 ;
      RECT 0.048 287.616 46.882 287.712 ;
      RECT 0.048 288.384 46.882 288.480 ;
      RECT 0.048 289.152 46.882 289.248 ;
      RECT 0.048 289.920 46.882 290.016 ;
      RECT 0.048 290.688 46.882 290.784 ;
      RECT 0.048 291.456 46.882 291.552 ;
      RECT 0.048 292.224 46.882 292.320 ;
      RECT 0.048 292.992 46.882 293.088 ;
      RECT 0.048 293.760 46.882 293.856 ;
      RECT 0.048 294.528 46.882 294.624 ;
      RECT 0.048 295.296 46.882 295.392 ;
      RECT 0.048 296.064 46.882 296.160 ;
      RECT 0.048 296.832 46.882 296.928 ;
      RECT 0.048 297.600 46.882 297.696 ;
      RECT 0.048 298.368 46.882 298.464 ;
      RECT 0.048 299.136 46.882 299.232 ;
      RECT 0.048 299.904 46.882 300.000 ;
      RECT 0.048 300.672 46.882 300.768 ;
      RECT 0.048 301.440 46.882 301.536 ;
      RECT 0.048 302.208 46.882 302.304 ;
      RECT 0.048 302.976 46.882 303.072 ;
      RECT 0.048 303.744 46.882 303.840 ;
      RECT 0.048 304.512 46.882 304.608 ;
      RECT 0.048 305.280 46.882 305.376 ;
      RECT 0.048 306.048 46.882 306.144 ;
      RECT 0.048 306.816 46.882 306.912 ;
      RECT 0.048 307.584 46.882 307.680 ;
      RECT 0.048 308.352 46.882 308.448 ;
      RECT 0.048 309.120 46.882 309.216 ;
      RECT 0.048 309.888 46.882 309.984 ;
      RECT 0.048 310.656 46.882 310.752 ;
      RECT 0.048 311.424 46.882 311.520 ;
      RECT 0.048 312.192 46.882 312.288 ;
      RECT 0.048 312.960 46.882 313.056 ;
      RECT 0.048 313.728 46.882 313.824 ;
      RECT 0.048 314.496 46.882 314.592 ;
      RECT 0.048 315.264 46.882 315.360 ;
      RECT 0.048 316.032 46.882 316.128 ;
      RECT 0.048 316.800 46.882 316.896 ;
      RECT 0.048 317.568 46.882 317.664 ;
      RECT 0.048 318.336 46.882 318.432 ;
      RECT 0.048 319.104 46.882 319.200 ;
      RECT 0.048 319.872 46.882 319.968 ;
      RECT 0.048 320.640 46.882 320.736 ;
      RECT 0.048 321.408 46.882 321.504 ;
      RECT 0.048 322.176 46.882 322.272 ;
      RECT 0.048 322.944 46.882 323.040 ;
      RECT 0.048 323.712 46.882 323.808 ;
      RECT 0.048 324.480 46.882 324.576 ;
      RECT 0.048 325.248 46.882 325.344 ;
      RECT 0.048 326.016 46.882 326.112 ;
      RECT 0.048 326.784 46.882 326.880 ;
      RECT 0.048 327.552 46.882 327.648 ;
      RECT 0.048 328.320 46.882 328.416 ;
      RECT 0.048 329.088 46.882 329.184 ;
      RECT 0.048 329.856 46.882 329.952 ;
      RECT 0.048 330.624 46.882 330.720 ;
      RECT 0.048 331.392 46.882 331.488 ;
      RECT 0.048 332.160 46.882 332.256 ;
      RECT 0.048 332.928 46.882 333.024 ;
    END
  END VDD
  OBS
    LAYER M1 ;
    RECT 0 0 46.930 333.200 ;
    LAYER M2 ;
    RECT 0 0 46.930 333.200 ;
    LAYER M3 ;
    RECT 0 0 46.930 333.200 ;
    LAYER M4 ;
    RECT 0 0 46.930 333.200 ;
  END
END fakeram7_dp_8196x32

END LIBRARY
